###############################################################
#  Generated by:      Cadence Innovus 21.35-s114_1
#  OS:                Linux x86_64(Host ID pc231.ee.hacettepe.edu.tr)
#  Generated on:      Wed Dec 24 12:11:23 2025
#  Design:            memory_macro
#  Command:           write_lef_abstract -5.7 outputs/memory_macro/memory_macro.lef
###############################################################

VERSION 5.7 ;

BUSBITCHARS "[]" ;
DIVIDERCHAR "/" ;

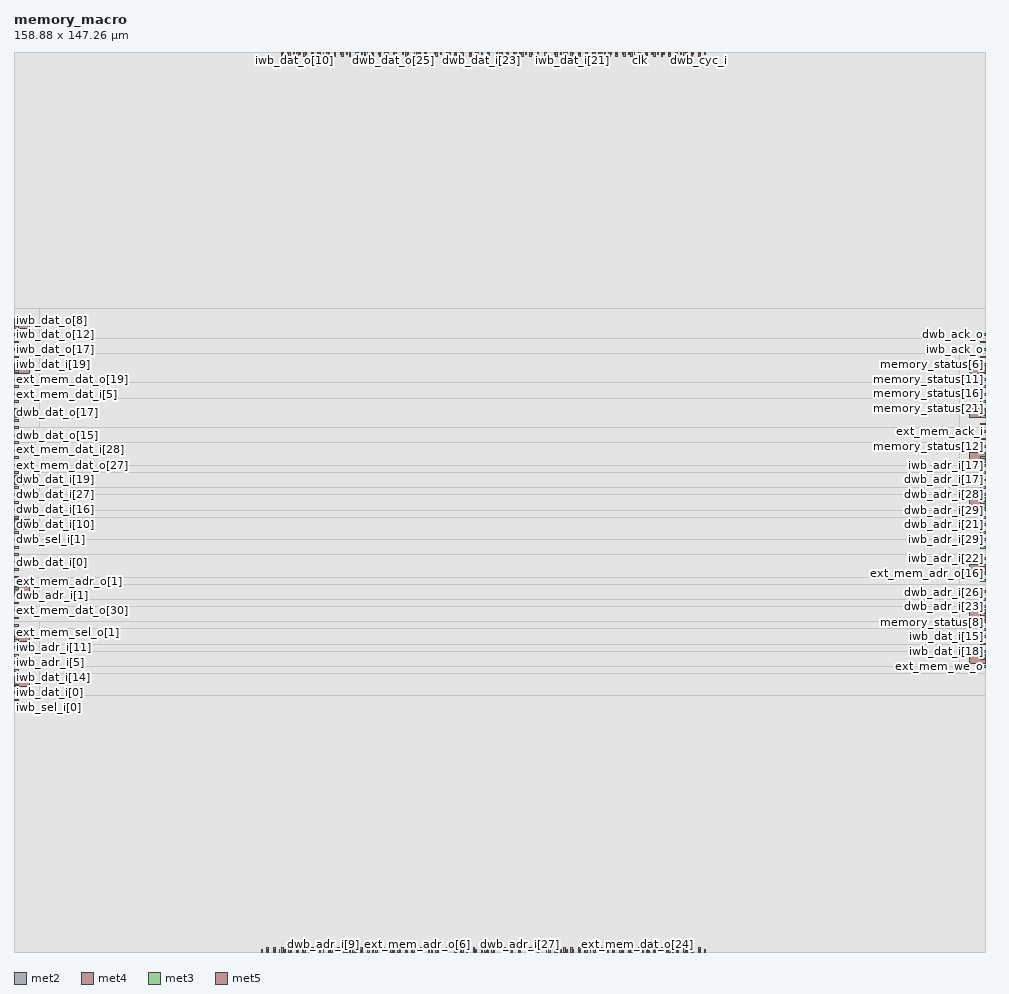
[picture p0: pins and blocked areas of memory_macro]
MACRO memory_macro
  CLASS BLOCK ;
  SIZE 158.880000 BY 147.260000 ;
  FOREIGN memory_macro 0.000000 0.000000 ;
  ORIGIN 0 0 ;
  SYMMETRY X Y R90 ;
  PIN clk
    DIRECTION INPUT ;
    USE SIGNAL ;
    PORT
      LAYER met2 ;
        RECT 102.410000 146.775000 102.550000 147.260000 ;
    END
  END clk
  PIN rst_n
    DIRECTION INPUT ;
    USE SIGNAL ;
    PORT
      LAYER met4 ;
        RECT 109.560000 146.460000 109.860000 147.260000 ;
    END
  END rst_n
  PIN iwb_adr_i[31]
    DIRECTION INPUT ;
    USE SIGNAL ;
    PORT
      LAYER met2 ;
        RECT 85.610000 146.775000 85.750000 147.260000 ;
    END
  END iwb_adr_i[31]
  PIN iwb_adr_i[30]
    DIRECTION INPUT ;
    USE SIGNAL ;
    PORT
      LAYER met4 ;
        RECT 96.030000 0.000000 96.330000 0.800000 ;
    END
  END iwb_adr_i[30]
  PIN iwb_adr_i[29]
    DIRECTION INPUT ;
    USE SIGNAL ;
    PORT
      LAYER met3 ;
        RECT 158.080000 68.540000 158.880000 68.840000 ;
    END
  END iwb_adr_i[29]
  PIN iwb_adr_i[28]
    DIRECTION INPUT ;
    USE SIGNAL ;
    PORT
      LAYER met3 ;
        RECT 158.080000 78.300000 158.880000 78.600000 ;
    END
  END iwb_adr_i[28]
  PIN iwb_adr_i[27]
    DIRECTION INPUT ;
    USE SIGNAL ;
    PORT
      LAYER met3 ;
        RECT 158.080000 67.320000 158.880000 67.620000 ;
    END
  END iwb_adr_i[27]
  PIN iwb_adr_i[26]
    DIRECTION INPUT ;
    USE SIGNAL ;
    PORT
      LAYER met4 ;
        RECT 99.105000 0.000000 99.405000 0.800000 ;
    END
  END iwb_adr_i[26]
  PIN iwb_adr_i[25]
    DIRECTION INPUT ;
    USE SIGNAL ;
    PORT
      LAYER met4 ;
        RECT 102.180000 0.000000 102.480000 0.800000 ;
    END
  END iwb_adr_i[25]
  PIN iwb_adr_i[24]
    DIRECTION INPUT ;
    USE SIGNAL ;
    PORT
      LAYER met2 ;
        RECT 102.890000 0.000000 103.030000 0.485000 ;
    END
  END iwb_adr_i[24]
  PIN iwb_adr_i[23]
    DIRECTION INPUT ;
    USE SIGNAL ;
    PORT
      LAYER met4 ;
        RECT 103.410000 0.000000 103.710000 0.800000 ;
    END
  END iwb_adr_i[23]
  PIN iwb_adr_i[22]
    DIRECTION INPUT ;
    USE SIGNAL ;
    PORT
      LAYER met3 ;
        RECT 158.080000 64.270000 158.880000 64.570000 ;
    END
  END iwb_adr_i[22]
  PIN iwb_adr_i[21]
    DIRECTION INPUT ;
    USE SIGNAL ;
    PORT
      LAYER met3 ;
        RECT 158.080000 66.100000 158.880000 66.400000 ;
    END
  END iwb_adr_i[21]
  PIN iwb_adr_i[20]
    DIRECTION INPUT ;
    USE SIGNAL ;
    PORT
      LAYER met4 ;
        RECT 85.575000 146.460000 85.875000 147.260000 ;
    END
  END iwb_adr_i[20]
  PIN iwb_adr_i[19]
    DIRECTION INPUT ;
    USE SIGNAL ;
    PORT
      LAYER met3 ;
        RECT 158.080000 55.120000 158.880000 55.420000 ;
    END
  END iwb_adr_i[19]
  PIN iwb_adr_i[18]
    DIRECTION INPUT ;
    USE SIGNAL ;
    PORT
      LAYER met5 ;
        RECT 156.380000 54.470000 158.880000 56.070000 ;
    END
  END iwb_adr_i[18]
  PIN iwb_adr_i[17]
    DIRECTION INPUT ;
    USE SIGNAL ;
    PORT
      LAYER met3 ;
        RECT 158.080000 79.520000 158.880000 79.820000 ;
    END
  END iwb_adr_i[17]
  PIN iwb_adr_i[16]
    DIRECTION INPUT ;
    USE SIGNAL ;
    PORT
      LAYER met4 ;
        RECT 104.640000 0.000000 104.940000 0.800000 ;
    END
  END iwb_adr_i[16]
  PIN iwb_adr_i[15]
    DIRECTION INPUT ;
    USE SIGNAL ;
    PORT
      LAYER met4 ;
        RECT 105.870000 0.000000 106.170000 0.800000 ;
    END
  END iwb_adr_i[15]
  PIN iwb_adr_i[14]
    DIRECTION INPUT ;
    USE SIGNAL ;
    PORT
      LAYER met4 ;
        RECT 51.750000 0.000000 52.050000 0.800000 ;
    END
  END iwb_adr_i[14]
  PIN iwb_adr_i[13]
    DIRECTION INPUT ;
    USE SIGNAL ;
    PORT
      LAYER met5 ;
        RECT 0.000000 50.810000 2.500000 52.410000 ;
    END
  END iwb_adr_i[13]
  PIN iwb_adr_i[12]
    DIRECTION INPUT ;
    USE SIGNAL ;
    PORT
      LAYER met2 ;
        RECT 51.530000 0.000000 51.670000 0.485000 ;
    END
  END iwb_adr_i[12]
  PIN iwb_adr_i[11]
    DIRECTION INPUT ;
    USE SIGNAL ;
    PORT
      LAYER met3 ;
        RECT 0.000000 50.850000 0.800000 51.150000 ;
    END
  END iwb_adr_i[11]
  PIN iwb_adr_i[10]
    DIRECTION INPUT ;
    USE SIGNAL ;
    PORT
      LAYER met2 ;
        RECT 106.730000 0.000000 106.870000 0.485000 ;
    END
  END iwb_adr_i[10]
  PIN iwb_adr_i[9]
    DIRECTION INPUT ;
    USE SIGNAL ;
    PORT
      LAYER met3 ;
        RECT 0.000000 49.630000 0.800000 49.930000 ;
    END
  END iwb_adr_i[9]
  PIN iwb_adr_i[8]
    DIRECTION INPUT ;
    USE SIGNAL ;
    PORT
      LAYER met3 ;
        RECT 0.000000 93.550000 0.800000 93.850000 ;
    END
  END iwb_adr_i[8]
  PIN iwb_adr_i[7]
    DIRECTION INPUT ;
    USE SIGNAL ;
    PORT
      LAYER met4 ;
        RECT 107.100000 0.000000 107.400000 0.800000 ;
    END
  END iwb_adr_i[7]
  PIN iwb_adr_i[6]
    DIRECTION INPUT ;
    USE SIGNAL ;
    PORT
      LAYER met4 ;
        RECT 48.675000 0.000000 48.975000 0.800000 ;
    END
  END iwb_adr_i[6]
  PIN iwb_adr_i[5]
    DIRECTION INPUT ;
    USE SIGNAL ;
    PORT
      LAYER met3 ;
        RECT 0.000000 48.410000 0.800000 48.710000 ;
    END
  END iwb_adr_i[5]
  PIN iwb_adr_i[4]
    DIRECTION INPUT ;
    USE SIGNAL ;
    PORT
      LAYER met2 ;
        RECT 48.170000 0.000000 48.310000 0.485000 ;
    END
  END iwb_adr_i[4]
  PIN iwb_adr_i[3]
    DIRECTION INPUT ;
    USE SIGNAL ;
    PORT
      LAYER met2 ;
        RECT 108.650000 0.000000 108.790000 0.485000 ;
    END
  END iwb_adr_i[3]
  PIN iwb_adr_i[2]
    DIRECTION INPUT ;
    USE SIGNAL ;
    PORT
      LAYER met4 ;
        RECT 108.330000 0.000000 108.630000 0.800000 ;
    END
  END iwb_adr_i[2]
  PIN iwb_adr_i[1]
    DIRECTION INPUT ;
    USE SIGNAL ;
    PORT
      LAYER met4 ;
        RECT 47.445000 0.000000 47.745000 0.800000 ;
    END
  END iwb_adr_i[1]
  PIN iwb_adr_i[0]
    DIRECTION INPUT ;
    USE SIGNAL ;
    PORT
      LAYER met4 ;
        RECT 109.560000 0.000000 109.860000 0.800000 ;
    END
  END iwb_adr_i[0]
  PIN iwb_dat_o[31]
    DIRECTION OUTPUT ;
    USE SIGNAL ;
    PORT
      LAYER met4 ;
        RECT 91.110000 146.460000 91.410000 147.260000 ;
    END
  END iwb_dat_o[31]
  PIN iwb_dat_o[30]
    DIRECTION OUTPUT ;
    USE SIGNAL ;
    PORT
      LAYER met4 ;
        RECT 49.905000 146.460000 50.205000 147.260000 ;
    END
  END iwb_dat_o[30]
  PIN iwb_dat_o[29]
    DIRECTION OUTPUT ;
    USE SIGNAL ;
    PORT
      LAYER met2 ;
        RECT 49.610000 146.775000 49.750000 147.260000 ;
    END
  END iwb_dat_o[29]
  PIN iwb_dat_o[28]
    DIRECTION OUTPUT ;
    USE SIGNAL ;
    PORT
      LAYER met3 ;
        RECT 0.000000 97.210000 0.800000 97.510000 ;
    END
  END iwb_dat_o[28]
  PIN iwb_dat_o[27]
    DIRECTION OUTPUT ;
    USE SIGNAL ;
    PORT
      LAYER met2 ;
        RECT 92.330000 146.775000 92.470000 147.260000 ;
    END
  END iwb_dat_o[27]
  PIN iwb_dat_o[26]
    DIRECTION OUTPUT ;
    USE SIGNAL ;
    PORT
      LAYER met4 ;
        RECT 92.340000 146.460000 92.640000 147.260000 ;
    END
  END iwb_dat_o[26]
  PIN iwb_dat_o[25]
    DIRECTION OUTPUT ;
    USE SIGNAL ;
    PORT
      LAYER met2 ;
        RECT 48.650000 146.775000 48.790000 147.260000 ;
    END
  END iwb_dat_o[25]
  PIN iwb_dat_o[24]
    DIRECTION OUTPUT ;
    USE SIGNAL ;
    PORT
      LAYER met4 ;
        RECT 48.675000 146.460000 48.975000 147.260000 ;
    END
  END iwb_dat_o[24]
  PIN iwb_dat_o[23]
    DIRECTION OUTPUT ;
    USE SIGNAL ;
    PORT
      LAYER met4 ;
        RECT 93.570000 146.460000 93.870000 147.260000 ;
    END
  END iwb_dat_o[23]
  PIN iwb_dat_o[22]
    DIRECTION OUTPUT ;
    USE SIGNAL ;
    PORT
      LAYER met2 ;
        RECT 94.730000 146.775000 94.870000 147.260000 ;
    END
  END iwb_dat_o[22]
  PIN iwb_dat_o[21]
    DIRECTION OUTPUT ;
    USE SIGNAL ;
    PORT
      LAYER met3 ;
        RECT 0.000000 98.430000 0.800000 98.730000 ;
    END
  END iwb_dat_o[21]
  PIN iwb_dat_o[20]
    DIRECTION OUTPUT ;
    USE SIGNAL ;
    PORT
      LAYER met2 ;
        RECT 47.690000 146.775000 47.830000 147.260000 ;
    END
  END iwb_dat_o[20]
  PIN iwb_dat_o[19]
    DIRECTION OUTPUT ;
    USE SIGNAL ;
    PORT
      LAYER met4 ;
        RECT 94.800000 146.460000 95.100000 147.260000 ;
    END
  END iwb_dat_o[19]
  PIN iwb_dat_o[18]
    DIRECTION OUTPUT ;
    USE SIGNAL ;
    PORT
      LAYER met4 ;
        RECT 47.445000 146.460000 47.745000 147.260000 ;
    END
  END iwb_dat_o[18]
  PIN iwb_dat_o[17]
    DIRECTION OUTPUT ;
    USE SIGNAL ;
    PORT
      LAYER met3 ;
        RECT 0.000000 99.650000 0.800000 99.950000 ;
    END
  END iwb_dat_o[17]
  PIN iwb_dat_o[16]
    DIRECTION OUTPUT ;
    USE SIGNAL ;
    PORT
      LAYER met4 ;
        RECT 96.030000 146.460000 96.330000 147.260000 ;
    END
  END iwb_dat_o[16]
  PIN iwb_dat_o[15]
    DIRECTION OUTPUT ;
    USE SIGNAL ;
    PORT
      LAYER met2 ;
        RECT 46.730000 146.775000 46.870000 147.260000 ;
    END
  END iwb_dat_o[15]
  PIN iwb_dat_o[14]
    DIRECTION OUTPUT ;
    USE SIGNAL ;
    PORT
      LAYER met2 ;
        RECT 96.650000 146.775000 96.790000 147.260000 ;
    END
  END iwb_dat_o[14]
  PIN iwb_dat_o[13]
    DIRECTION OUTPUT ;
    USE SIGNAL ;
    PORT
      LAYER met4 ;
        RECT 46.215000 146.460000 46.515000 147.260000 ;
    END
  END iwb_dat_o[13]
  PIN iwb_dat_o[12]
    DIRECTION OUTPUT ;
    USE SIGNAL ;
    PORT
      LAYER met3 ;
        RECT 0.000000 100.870000 0.800000 101.170000 ;
    END
  END iwb_dat_o[12]
  PIN iwb_dat_o[11]
    DIRECTION OUTPUT ;
    USE SIGNAL ;
    PORT
      LAYER met4 ;
        RECT 97.260000 146.460000 97.560000 147.260000 ;
    END
  END iwb_dat_o[11]
  PIN iwb_dat_o[10]
    DIRECTION OUTPUT ;
    USE SIGNAL ;
    PORT
      LAYER met2 ;
        RECT 45.770000 146.775000 45.910000 147.260000 ;
    END
  END iwb_dat_o[10]
  PIN iwb_dat_o[9]
    DIRECTION OUTPUT ;
    USE SIGNAL ;
    PORT
      LAYER met4 ;
        RECT 44.985000 146.460000 45.285000 147.260000 ;
    END
  END iwb_dat_o[9]
  PIN iwb_dat_o[8]
    DIRECTION OUTPUT ;
    USE SIGNAL ;
    PORT
      LAYER met3 ;
        RECT 0.000000 102.090000 0.800000 102.390000 ;
    END
  END iwb_dat_o[8]
  PIN iwb_dat_o[7]
    DIRECTION OUTPUT ;
    USE SIGNAL ;
    PORT
      LAYER met2 ;
        RECT 97.610000 146.775000 97.750000 147.260000 ;
    END
  END iwb_dat_o[7]
  PIN iwb_dat_o[6]
    DIRECTION OUTPUT ;
    USE SIGNAL ;
    PORT
      LAYER met2 ;
        RECT 44.810000 146.775000 44.950000 147.260000 ;
    END
  END iwb_dat_o[6]
  PIN iwb_dat_o[5]
    DIRECTION OUTPUT ;
    USE SIGNAL ;
    PORT
      LAYER met5 ;
        RECT 0.000000 102.050000 2.500000 103.650000 ;
    END
  END iwb_dat_o[5]
  PIN iwb_dat_o[4]
    DIRECTION OUTPUT ;
    USE SIGNAL ;
    PORT
      LAYER met2 ;
        RECT 98.570000 146.775000 98.710000 147.260000 ;
    END
  END iwb_dat_o[4]
  PIN iwb_dat_o[3]
    DIRECTION OUTPUT ;
    USE SIGNAL ;
    PORT
      LAYER met2 ;
        RECT 43.850000 146.775000 43.990000 147.260000 ;
    END
  END iwb_dat_o[3]
  PIN iwb_dat_o[2]
    DIRECTION OUTPUT ;
    USE SIGNAL ;
    PORT
      LAYER met4 ;
        RECT 43.755000 146.460000 44.055000 147.260000 ;
    END
  END iwb_dat_o[2]
  PIN iwb_dat_o[1]
    DIRECTION OUTPUT ;
    USE SIGNAL ;
    PORT
      LAYER met4 ;
        RECT 98.490000 146.460000 98.790000 147.260000 ;
    END
  END iwb_dat_o[1]
  PIN iwb_dat_o[0]
    DIRECTION OUTPUT ;
    USE SIGNAL ;
    PORT
      LAYER met2 ;
        RECT 99.530000 146.775000 99.670000 147.260000 ;
    END
  END iwb_dat_o[0]
  PIN iwb_dat_i[31]
    DIRECTION INPUT ;
    USE SIGNAL ;
    PORT
      LAYER met3 ;
        RECT 0.000000 47.190000 0.800000 47.490000 ;
    END
  END iwb_dat_i[31]
  PIN iwb_dat_i[30]
    DIRECTION INPUT ;
    USE SIGNAL ;
    PORT
      LAYER met2 ;
        RECT 47.210000 0.000000 47.350000 0.485000 ;
    END
  END iwb_dat_i[30]
  PIN iwb_dat_i[29]
    DIRECTION INPUT ;
    USE SIGNAL ;
    PORT
      LAYER met2 ;
        RECT 52.490000 146.775000 52.630000 147.260000 ;
    END
  END iwb_dat_i[29]
  PIN iwb_dat_i[28]
    DIRECTION INPUT ;
    USE SIGNAL ;
    PORT
      LAYER met2 ;
        RECT 46.250000 0.000000 46.390000 0.485000 ;
    END
  END iwb_dat_i[28]
  PIN iwb_dat_i[27]
    DIRECTION INPUT ;
    USE SIGNAL ;
    PORT
      LAYER met4 ;
        RECT 52.365000 146.460000 52.665000 147.260000 ;
    END
  END iwb_dat_i[27]
  PIN iwb_dat_i[26]
    DIRECTION INPUT ;
    USE SIGNAL ;
    PORT
      LAYER met4 ;
        RECT 46.215000 0.000000 46.515000 0.800000 ;
    END
  END iwb_dat_i[26]
  PIN iwb_dat_i[25]
    DIRECTION INPUT ;
    USE SIGNAL ;
    PORT
      LAYER met3 ;
        RECT 158.080000 50.240000 158.880000 50.540000 ;
    END
  END iwb_dat_i[25]
  PIN iwb_dat_i[24]
    DIRECTION INPUT ;
    USE SIGNAL ;
    PORT
      LAYER met2 ;
        RECT 111.050000 0.000000 111.190000 0.485000 ;
    END
  END iwb_dat_i[24]
  PIN iwb_dat_i[23]
    DIRECTION INPUT ;
    USE SIGNAL ;
    PORT
      LAYER met4 ;
        RECT 89.880000 146.460000 90.180000 147.260000 ;
    END
  END iwb_dat_i[23]
  PIN iwb_dat_i[22]
    DIRECTION INPUT ;
    USE SIGNAL ;
    PORT
      LAYER met2 ;
        RECT 45.290000 0.000000 45.430000 0.485000 ;
    END
  END iwb_dat_i[22]
  PIN iwb_dat_i[21]
    DIRECTION INPUT ;
    USE SIGNAL ;
    PORT
      LAYER met2 ;
        RECT 91.370000 146.775000 91.510000 147.260000 ;
    END
  END iwb_dat_i[21]
  PIN iwb_dat_i[20]
    DIRECTION INPUT ;
    USE SIGNAL ;
    PORT
      LAYER met3 ;
        RECT 0.000000 45.970000 0.800000 46.270000 ;
    END
  END iwb_dat_i[20]
  PIN iwb_dat_i[19]
    DIRECTION INPUT ;
    USE SIGNAL ;
    PORT
      LAYER met3 ;
        RECT 0.000000 94.770000 0.800000 95.070000 ;
    END
  END iwb_dat_i[19]
  PIN iwb_dat_i[18]
    DIRECTION INPUT ;
    USE SIGNAL ;
    PORT
      LAYER met3 ;
        RECT 158.080000 49.020000 158.880000 49.320000 ;
    END
  END iwb_dat_i[18]
  PIN iwb_dat_i[17]
    DIRECTION INPUT ;
    USE SIGNAL ;
    PORT
      LAYER met4 ;
        RECT 44.985000 0.000000 45.285000 0.800000 ;
    END
  END iwb_dat_i[17]
  PIN iwb_dat_i[16]
    DIRECTION INPUT ;
    USE SIGNAL ;
    PORT
      LAYER met5 ;
        RECT 0.000000 94.730000 2.500000 96.330000 ;
    END
  END iwb_dat_i[16]
  PIN iwb_dat_i[15]
    DIRECTION INPUT ;
    USE SIGNAL ;
    PORT
      LAYER met3 ;
        RECT 158.080000 51.460000 158.880000 51.760000 ;
    END
  END iwb_dat_i[15]
  PIN iwb_dat_i[14]
    DIRECTION INPUT ;
    USE SIGNAL ;
    PORT
      LAYER met3 ;
        RECT 0.000000 44.750000 0.800000 45.050000 ;
    END
  END iwb_dat_i[14]
  PIN iwb_dat_i[13]
    DIRECTION INPUT ;
    USE SIGNAL ;
    PORT
      LAYER met2 ;
        RECT 44.330000 0.000000 44.470000 0.485000 ;
    END
  END iwb_dat_i[13]
  PIN iwb_dat_i[12]
    DIRECTION INPUT ;
    USE SIGNAL ;
    PORT
      LAYER met2 ;
        RECT 51.530000 146.775000 51.670000 147.260000 ;
    END
  END iwb_dat_i[12]
  PIN iwb_dat_i[11]
    DIRECTION INPUT ;
    USE SIGNAL ;
    PORT
      LAYER met4 ;
        RECT 110.790000 0.000000 111.090000 0.800000 ;
    END
  END iwb_dat_i[11]
  PIN iwb_dat_i[10]
    DIRECTION INPUT ;
    USE SIGNAL ;
    PORT
      LAYER met4 ;
        RECT 51.135000 146.460000 51.435000 147.260000 ;
    END
  END iwb_dat_i[10]
  PIN iwb_dat_i[9]
    DIRECTION INPUT ;
    USE SIGNAL ;
    PORT
      LAYER met4 ;
        RECT 43.755000 0.000000 44.055000 0.800000 ;
    END
  END iwb_dat_i[9]
  PIN iwb_dat_i[8]
    DIRECTION INPUT ;
    USE SIGNAL ;
    PORT
      LAYER met3 ;
        RECT 0.000000 43.530000 0.800000 43.830000 ;
    END
  END iwb_dat_i[8]
  PIN iwb_dat_i[7]
    DIRECTION INPUT ;
    USE SIGNAL ;
    PORT
      LAYER met5 ;
        RECT 0.000000 43.490000 2.500000 45.090000 ;
    END
  END iwb_dat_i[7]
  PIN iwb_dat_i[6]
    DIRECTION INPUT ;
    USE SIGNAL ;
    PORT
      LAYER met3 ;
        RECT 0.000000 95.990000 0.800000 96.290000 ;
    END
  END iwb_dat_i[6]
  PIN iwb_dat_i[5]
    DIRECTION INPUT ;
    USE SIGNAL ;
    PORT
      LAYER met2 ;
        RECT 50.570000 146.775000 50.710000 147.260000 ;
    END
  END iwb_dat_i[5]
  PIN iwb_dat_i[4]
    DIRECTION INPUT ;
    USE SIGNAL ;
    PORT
      LAYER met2 ;
        RECT 43.370000 0.000000 43.510000 0.485000 ;
    END
  END iwb_dat_i[4]
  PIN iwb_dat_i[3]
    DIRECTION INPUT ;
    USE SIGNAL ;
    PORT
      LAYER met3 ;
        RECT 158.080000 47.800000 158.880000 48.100000 ;
    END
  END iwb_dat_i[3]
  PIN iwb_dat_i[2]
    DIRECTION INPUT ;
    USE SIGNAL ;
    PORT
      LAYER met2 ;
        RECT 42.410000 0.000000 42.550000 0.485000 ;
    END
  END iwb_dat_i[2]
  PIN iwb_dat_i[1]
    DIRECTION INPUT ;
    USE SIGNAL ;
    PORT
      LAYER met4 ;
        RECT 42.525000 0.000000 42.825000 0.800000 ;
    END
  END iwb_dat_i[1]
  PIN iwb_dat_i[0]
    DIRECTION INPUT ;
    USE SIGNAL ;
    PORT
      LAYER met3 ;
        RECT 0.000000 42.310000 0.800000 42.610000 ;
    END
  END iwb_dat_i[0]
  PIN iwb_we_i
    DIRECTION INPUT ;
    USE SIGNAL ;
    PORT
      LAYER met2 ;
        RECT 40.490000 0.000000 40.630000 0.485000 ;
    END
  END iwb_we_i
  PIN iwb_sel_i[3]
    DIRECTION INPUT ;
    USE SIGNAL ;
    PORT
      LAYER met2 ;
        RECT 112.010000 0.000000 112.150000 0.485000 ;
    END
  END iwb_sel_i[3]
  PIN iwb_sel_i[2]
    DIRECTION INPUT ;
    USE SIGNAL ;
    PORT
      LAYER met2 ;
        RECT 41.450000 0.000000 41.590000 0.485000 ;
    END
  END iwb_sel_i[2]
  PIN iwb_sel_i[1]
    DIRECTION INPUT ;
    USE SIGNAL ;
    PORT
      LAYER met4 ;
        RECT 41.295000 0.000000 41.595000 0.800000 ;
    END
  END iwb_sel_i[1]
  PIN iwb_sel_i[0]
    DIRECTION INPUT ;
    USE SIGNAL ;
    PORT
      LAYER met3 ;
        RECT 0.000000 41.090000 0.800000 41.390000 ;
    END
  END iwb_sel_i[0]
  PIN iwb_cyc_i
    DIRECTION INPUT ;
    USE SIGNAL ;
    PORT
      LAYER met2 ;
        RECT 111.050000 146.775000 111.190000 147.260000 ;
    END
  END iwb_cyc_i
  PIN iwb_stb_i
    DIRECTION INPUT ;
    USE SIGNAL ;
    PORT
      LAYER met4 ;
        RECT 110.790000 146.460000 111.090000 147.260000 ;
    END
  END iwb_stb_i
  PIN iwb_ack_o
    DIRECTION OUTPUT ;
    USE SIGNAL ;
    PORT
      LAYER met3 ;
        RECT 158.080000 99.650000 158.880000 99.950000 ;
    END
  END iwb_ack_o
  PIN iwb_err_o
    DIRECTION OUTPUT ;
    USE SIGNAL ;
    PORT
      LAYER met3 ;
        RECT 158.080000 98.430000 158.880000 98.730000 ;
    END
  END iwb_err_o
  PIN dwb_adr_i[31]
    DIRECTION INPUT ;
    USE SIGNAL ;
    PORT
      LAYER met3 ;
        RECT 158.080000 82.570000 158.880000 82.870000 ;
    END
  END dwb_adr_i[31]
  PIN dwb_adr_i[30]
    DIRECTION INPUT ;
    USE SIGNAL ;
    PORT
      LAYER met2 ;
        RECT 84.170000 0.000000 84.310000 0.485000 ;
    END
  END dwb_adr_i[30]
  PIN dwb_adr_i[29]
    DIRECTION INPUT ;
    USE SIGNAL ;
    PORT
      LAYER met3 ;
        RECT 158.080000 70.980000 158.880000 71.280000 ;
    END
  END dwb_adr_i[29]
  PIN dwb_adr_i[28]
    DIRECTION INPUT ;
    USE SIGNAL ;
    PORT
      LAYER met3 ;
        RECT 158.080000 75.860000 158.880000 76.160000 ;
    END
  END dwb_adr_i[28]
  PIN dwb_adr_i[27]
    DIRECTION INPUT ;
    USE SIGNAL ;
    PORT
      LAYER met2 ;
        RECT 82.730000 0.000000 82.870000 0.485000 ;
    END
  END dwb_adr_i[27]
  PIN dwb_adr_i[26]
    DIRECTION INPUT ;
    USE SIGNAL ;
    PORT
      LAYER met3 ;
        RECT 158.080000 57.560000 158.880000 57.860000 ;
    END
  END dwb_adr_i[26]
  PIN dwb_adr_i[25]
    DIRECTION INPUT ;
    USE SIGNAL ;
    PORT
      LAYER met2 ;
        RECT 89.450000 0.000000 89.590000 0.485000 ;
    END
  END dwb_adr_i[25]
  PIN dwb_adr_i[24]
    DIRECTION INPUT ;
    USE SIGNAL ;
    PORT
      LAYER met2 ;
        RECT 91.370000 0.000000 91.510000 0.485000 ;
    END
  END dwb_adr_i[24]
  PIN dwb_adr_i[23]
    DIRECTION INPUT ;
    USE SIGNAL ;
    PORT
      LAYER met3 ;
        RECT 158.080000 56.340000 158.880000 56.640000 ;
    END
  END dwb_adr_i[23]
  PIN dwb_adr_i[22]
    DIRECTION INPUT ;
    USE SIGNAL ;
    PORT
      LAYER met4 ;
        RECT 88.650000 0.000000 88.950000 0.800000 ;
    END
  END dwb_adr_i[22]
  PIN dwb_adr_i[21]
    DIRECTION INPUT ;
    USE SIGNAL ;
    PORT
      LAYER met3 ;
        RECT 158.080000 69.760000 158.880000 70.060000 ;
    END
  END dwb_adr_i[21]
  PIN dwb_adr_i[20]
    DIRECTION INPUT ;
    USE SIGNAL ;
    PORT
      LAYER met2 ;
        RECT 79.850000 0.000000 79.990000 0.485000 ;
    END
  END dwb_adr_i[20]
  PIN dwb_adr_i[19]
    DIRECTION INPUT ;
    USE SIGNAL ;
    PORT
      LAYER met3 ;
        RECT 158.080000 63.050000 158.880000 63.350000 ;
    END
  END dwb_adr_i[19]
  PIN dwb_adr_i[18]
    DIRECTION INPUT ;
    USE SIGNAL ;
    PORT
      LAYER met2 ;
        RECT 81.290000 0.000000 81.430000 0.485000 ;
    END
  END dwb_adr_i[18]
  PIN dwb_adr_i[17]
    DIRECTION INPUT ;
    USE SIGNAL ;
    PORT
      LAYER met3 ;
        RECT 158.080000 77.080000 158.880000 77.380000 ;
    END
  END dwb_adr_i[17]
  PIN dwb_adr_i[16]
    DIRECTION INPUT ;
    USE SIGNAL ;
    PORT
      LAYER met5 ;
        RECT 156.380000 61.790000 158.880000 63.390000 ;
    END
  END dwb_adr_i[16]
  PIN dwb_adr_i[15]
    DIRECTION INPUT ;
    USE SIGNAL ;
    PORT
      LAYER met2 ;
        RECT 99.530000 0.000000 99.670000 0.485000 ;
    END
  END dwb_adr_i[15]
  PIN dwb_adr_i[14]
    DIRECTION INPUT ;
    USE SIGNAL ;
    PORT
      LAYER met2 ;
        RECT 60.170000 0.000000 60.310000 0.485000 ;
    END
  END dwb_adr_i[14]
  PIN dwb_adr_i[13]
    DIRECTION INPUT ;
    USE SIGNAL ;
    PORT
      LAYER met2 ;
        RECT 75.530000 0.000000 75.670000 0.485000 ;
    END
  END dwb_adr_i[13]
  PIN dwb_adr_i[12]
    DIRECTION INPUT ;
    USE SIGNAL ;
    PORT
      LAYER met2 ;
        RECT 64.010000 0.000000 64.150000 0.485000 ;
    END
  END dwb_adr_i[12]
  PIN dwb_adr_i[11]
    DIRECTION INPUT ;
    USE SIGNAL ;
    PORT
      LAYER met2 ;
        RECT 72.170000 0.000000 72.310000 0.485000 ;
    END
  END dwb_adr_i[11]
  PIN dwb_adr_i[10]
    DIRECTION INPUT ;
    USE SIGNAL ;
    PORT
      LAYER met2 ;
        RECT 87.050000 0.000000 87.190000 0.485000 ;
    END
  END dwb_adr_i[10]
  PIN dwb_adr_i[9]
    DIRECTION INPUT ;
    USE SIGNAL ;
    PORT
      LAYER met2 ;
        RECT 50.570000 0.000000 50.710000 0.485000 ;
    END
  END dwb_adr_i[9]
  PIN dwb_adr_i[8]
    DIRECTION INPUT ;
    USE SIGNAL ;
    PORT
      LAYER met2 ;
        RECT 72.170000 146.775000 72.310000 147.260000 ;
    END
  END dwb_adr_i[8]
  PIN dwb_adr_i[7]
    DIRECTION INPUT ;
    USE SIGNAL ;
    PORT
      LAYER met2 ;
        RECT 107.690000 0.000000 107.830000 0.485000 ;
    END
  END dwb_adr_i[7]
  PIN dwb_adr_i[6]
    DIRECTION INPUT ;
    USE SIGNAL ;
    PORT
      LAYER met2 ;
        RECT 68.330000 0.000000 68.470000 0.485000 ;
    END
  END dwb_adr_i[6]
  PIN dwb_adr_i[5]
    DIRECTION INPUT ;
    USE SIGNAL ;
    PORT
      LAYER met2 ;
        RECT 66.890000 0.000000 67.030000 0.485000 ;
    END
  END dwb_adr_i[5]
  PIN dwb_adr_i[4]
    DIRECTION INPUT ;
    USE SIGNAL ;
    PORT
      LAYER met4 ;
        RECT 60.360000 0.000000 60.660000 0.800000 ;
    END
  END dwb_adr_i[4]
  PIN dwb_adr_i[3]
    DIRECTION INPUT ;
    USE SIGNAL ;
    PORT
      LAYER met2 ;
        RECT 95.690000 0.000000 95.830000 0.485000 ;
    END
  END dwb_adr_i[3]
  PIN dwb_adr_i[2]
    DIRECTION INPUT ;
    USE SIGNAL ;
    PORT
      LAYER met4 ;
        RECT 91.110000 0.000000 91.410000 0.800000 ;
    END
  END dwb_adr_i[2]
  PIN dwb_adr_i[1]
    DIRECTION INPUT ;
    USE SIGNAL ;
    PORT
      LAYER met3 ;
        RECT 0.000000 58.170000 0.800000 58.470000 ;
    END
  END dwb_adr_i[1]
  PIN dwb_adr_i[0]
    DIRECTION INPUT ;
    USE SIGNAL ;
    PORT
      LAYER met4 ;
        RECT 82.500000 0.000000 82.800000 0.800000 ;
    END
  END dwb_adr_i[0]
  PIN dwb_dat_o[31]
    DIRECTION OUTPUT ;
    USE SIGNAL ;
    PORT
      LAYER met4 ;
        RECT 75.735000 146.460000 76.035000 147.260000 ;
    END
  END dwb_dat_o[31]
  PIN dwb_dat_o[30]
    DIRECTION OUTPUT ;
    USE SIGNAL ;
    PORT
      LAYER met2 ;
        RECT 67.370000 146.775000 67.510000 147.260000 ;
    END
  END dwb_dat_o[30]
  PIN dwb_dat_o[29]
    DIRECTION OUTPUT ;
    USE SIGNAL ;
    PORT
      LAYER met2 ;
        RECT 58.730000 146.775000 58.870000 147.260000 ;
    END
  END dwb_dat_o[29]
  PIN dwb_dat_o[28]
    DIRECTION OUTPUT ;
    USE SIGNAL ;
    PORT
      LAYER met3 ;
        RECT 0.000000 85.620000 0.800000 85.920000 ;
    END
  END dwb_dat_o[28]
  PIN dwb_dat_o[27]
    DIRECTION OUTPUT ;
    USE SIGNAL ;
    PORT
      LAYER met2 ;
        RECT 78.890000 146.775000 79.030000 147.260000 ;
    END
  END dwb_dat_o[27]
  PIN dwb_dat_o[26]
    DIRECTION OUTPUT ;
    USE SIGNAL ;
    PORT
      LAYER met4 ;
        RECT 79.425000 146.460000 79.725000 147.260000 ;
    END
  END dwb_dat_o[26]
  PIN dwb_dat_o[25]
    DIRECTION OUTPUT ;
    USE SIGNAL ;
    PORT
      LAYER met2 ;
        RECT 62.090000 146.775000 62.230000 147.260000 ;
    END
  END dwb_dat_o[25]
  PIN dwb_dat_o[24]
    DIRECTION OUTPUT ;
    USE SIGNAL ;
    PORT
      LAYER met2 ;
        RECT 73.130000 146.775000 73.270000 147.260000 ;
    END
  END dwb_dat_o[24]
  PIN dwb_dat_o[23]
    DIRECTION OUTPUT ;
    USE SIGNAL ;
    PORT
      LAYER met2 ;
        RECT 88.490000 146.775000 88.630000 147.260000 ;
    END
  END dwb_dat_o[23]
  PIN dwb_dat_o[22]
    DIRECTION OUTPUT ;
    USE SIGNAL ;
    PORT
      LAYER met2 ;
        RECT 77.450000 146.775000 77.590000 147.260000 ;
    END
  END dwb_dat_o[22]
  PIN dwb_dat_o[21]
    DIRECTION OUTPUT ;
    USE SIGNAL ;
    PORT
      LAYER met2 ;
        RECT 53.450000 146.775000 53.590000 147.260000 ;
    END
  END dwb_dat_o[21]
  PIN dwb_dat_o[20]
    DIRECTION OUTPUT ;
    USE SIGNAL ;
    PORT
      LAYER met4 ;
        RECT 62.205000 146.460000 62.505000 147.260000 ;
    END
  END dwb_dat_o[20]
  PIN dwb_dat_o[19]
    DIRECTION OUTPUT ;
    USE SIGNAL ;
    PORT
      LAYER met4 ;
        RECT 88.650000 146.460000 88.950000 147.260000 ;
    END
  END dwb_dat_o[19]
  PIN dwb_dat_o[18]
    DIRECTION OUTPUT ;
    USE SIGNAL ;
    PORT
      LAYER met4 ;
        RECT 67.125000 146.460000 67.425000 147.260000 ;
    END
  END dwb_dat_o[18]
  PIN dwb_dat_o[17]
    DIRECTION OUTPUT ;
    USE SIGNAL ;
    PORT
      LAYER met3 ;
        RECT 0.000000 88.060000 0.800000 88.360000 ;
    END
  END dwb_dat_o[17]
  PIN dwb_dat_o[16]
    DIRECTION OUTPUT ;
    USE SIGNAL ;
    PORT
      LAYER met4 ;
        RECT 77.580000 146.460000 77.880000 147.260000 ;
    END
  END dwb_dat_o[16]
  PIN dwb_dat_o[15]
    DIRECTION OUTPUT ;
    USE SIGNAL ;
    PORT
      LAYER met3 ;
        RECT 0.000000 84.400000 0.800000 84.700000 ;
    END
  END dwb_dat_o[15]
  PIN dwb_dat_o[14]
    DIRECTION OUTPUT ;
    USE SIGNAL ;
    PORT
      LAYER met4 ;
        RECT 73.275000 146.460000 73.575000 147.260000 ;
    END
  END dwb_dat_o[14]
  PIN dwb_dat_o[13]
    DIRECTION OUTPUT ;
    USE SIGNAL ;
    PORT
      LAYER met2 ;
        RECT 68.810000 146.775000 68.950000 147.260000 ;
    END
  END dwb_dat_o[13]
  PIN dwb_dat_o[12]
    DIRECTION OUTPUT ;
    USE SIGNAL ;
    PORT
      LAYER met2 ;
        RECT 63.530000 146.775000 63.670000 147.260000 ;
    END
  END dwb_dat_o[12]
  PIN dwb_dat_o[11]
    DIRECTION OUTPUT ;
    USE SIGNAL ;
    PORT
      LAYER met2 ;
        RECT 81.770000 146.775000 81.910000 147.260000 ;
    END
  END dwb_dat_o[11]
  PIN dwb_dat_o[10]
    DIRECTION OUTPUT ;
    USE SIGNAL ;
    PORT
      LAYER met4 ;
        RECT 68.970000 146.460000 69.270000 147.260000 ;
    END
  END dwb_dat_o[10]
  PIN dwb_dat_o[9]
    DIRECTION OUTPUT ;
    USE SIGNAL ;
    PORT
      LAYER met2 ;
        RECT 60.650000 146.775000 60.790000 147.260000 ;
    END
  END dwb_dat_o[9]
  PIN dwb_dat_o[8]
    DIRECTION OUTPUT ;
    USE SIGNAL ;
    PORT
      LAYER met2 ;
        RECT 66.410000 146.775000 66.550000 147.260000 ;
    END
  END dwb_dat_o[8]
  PIN dwb_dat_o[7]
    DIRECTION OUTPUT ;
    USE SIGNAL ;
    PORT
      LAYER met2 ;
        RECT 95.690000 146.775000 95.830000 147.260000 ;
    END
  END dwb_dat_o[7]
  PIN dwb_dat_o[6]
    DIRECTION OUTPUT ;
    USE SIGNAL ;
    PORT
      LAYER met2 ;
        RECT 57.770000 146.775000 57.910000 147.260000 ;
    END
  END dwb_dat_o[6]
  PIN dwb_dat_o[5]
    DIRECTION OUTPUT ;
    USE SIGNAL ;
    PORT
      LAYER met5 ;
        RECT 0.000000 87.410000 2.500000 89.010000 ;
    END
  END dwb_dat_o[5]
  PIN dwb_dat_o[4]
    DIRECTION OUTPUT ;
    USE SIGNAL ;
    PORT
      LAYER met4 ;
        RECT 81.885000 146.460000 82.185000 147.260000 ;
    END
  END dwb_dat_o[4]
  PIN dwb_dat_o[3]
    DIRECTION OUTPUT ;
    USE SIGNAL ;
    PORT
      LAYER met4 ;
        RECT 65.895000 146.460000 66.195000 147.260000 ;
    END
  END dwb_dat_o[3]
  PIN dwb_dat_o[2]
    DIRECTION OUTPUT ;
    USE SIGNAL ;
    PORT
      LAYER met4 ;
        RECT 53.595000 146.460000 53.895000 147.260000 ;
    END
  END dwb_dat_o[2]
  PIN dwb_dat_o[1]
    DIRECTION OUTPUT ;
    USE SIGNAL ;
    PORT
      LAYER met2 ;
        RECT 87.050000 146.775000 87.190000 147.260000 ;
    END
  END dwb_dat_o[1]
  PIN dwb_dat_o[0]
    DIRECTION OUTPUT ;
    USE SIGNAL ;
    PORT
      LAYER met2 ;
        RECT 79.850000 146.775000 79.990000 147.260000 ;
    END
  END dwb_dat_o[0]
  PIN dwb_dat_i[31]
    DIRECTION INPUT ;
    USE SIGNAL ;
    PORT
      LAYER met2 ;
        RECT 73.130000 0.000000 73.270000 0.485000 ;
    END
  END dwb_dat_i[31]
  PIN dwb_dat_i[30]
    DIRECTION INPUT ;
    USE SIGNAL ;
    PORT
      LAYER met5 ;
        RECT 0.000000 58.130000 2.500000 59.730000 ;
    END
  END dwb_dat_i[30]
  PIN dwb_dat_i[29]
    DIRECTION INPUT ;
    USE SIGNAL ;
    PORT
      LAYER met3 ;
        RECT 0.000000 75.860000 0.800000 76.160000 ;
    END
  END dwb_dat_i[29]
  PIN dwb_dat_i[28]
    DIRECTION INPUT ;
    USE SIGNAL ;
    PORT
      LAYER met2 ;
        RECT 55.850000 0.000000 55.990000 0.485000 ;
    END
  END dwb_dat_i[28]
  PIN dwb_dat_i[27]
    DIRECTION INPUT ;
    USE SIGNAL ;
    PORT
      LAYER met3 ;
        RECT 0.000000 74.640000 0.800000 74.940000 ;
    END
  END dwb_dat_i[27]
  PIN dwb_dat_i[26]
    DIRECTION INPUT ;
    USE SIGNAL ;
    PORT
      LAYER met3 ;
        RECT 0.000000 70.980000 0.800000 71.280000 ;
    END
  END dwb_dat_i[26]
  PIN dwb_dat_i[25]
    DIRECTION INPUT ;
    USE SIGNAL ;
    PORT
      LAYER met4 ;
        RECT 80.040000 0.000000 80.340000 0.800000 ;
    END
  END dwb_dat_i[25]
  PIN dwb_dat_i[24]
    DIRECTION INPUT ;
    USE SIGNAL ;
    PORT
      LAYER met2 ;
        RECT 100.490000 0.000000 100.630000 0.485000 ;
    END
  END dwb_dat_i[24]
  PIN dwb_dat_i[23]
    DIRECTION INPUT ;
    USE SIGNAL ;
    PORT
      LAYER met2 ;
        RECT 76.490000 146.775000 76.630000 147.260000 ;
    END
  END dwb_dat_i[23]
  PIN dwb_dat_i[22]
    DIRECTION INPUT ;
    USE SIGNAL ;
    PORT
      LAYER met2 ;
        RECT 69.290000 0.000000 69.430000 0.485000 ;
    END
  END dwb_dat_i[22]
  PIN dwb_dat_i[21]
    DIRECTION INPUT ;
    USE SIGNAL ;
    PORT
      LAYER met4 ;
        RECT 75.120000 0.000000 75.420000 0.800000 ;
    END
  END dwb_dat_i[21]
  PIN dwb_dat_i[20]
    DIRECTION INPUT ;
    USE SIGNAL ;
    PORT
      LAYER met2 ;
        RECT 70.730000 0.000000 70.870000 0.485000 ;
    END
  END dwb_dat_i[20]
  PIN dwb_dat_i[19]
    DIRECTION INPUT ;
    USE SIGNAL ;
    PORT
      LAYER met3 ;
        RECT 0.000000 77.080000 0.800000 77.380000 ;
    END
  END dwb_dat_i[19]
  PIN dwb_dat_i[18]
    DIRECTION INPUT ;
    USE SIGNAL ;
    PORT
      LAYER met2 ;
        RECT 103.850000 0.000000 103.990000 0.485000 ;
    END
  END dwb_dat_i[18]
  PIN dwb_dat_i[17]
    DIRECTION INPUT ;
    USE SIGNAL ;
    PORT
      LAYER met3 ;
        RECT 0.000000 62.440000 0.800000 62.740000 ;
    END
  END dwb_dat_i[17]
  PIN dwb_dat_i[16]
    DIRECTION INPUT ;
    USE SIGNAL ;
    PORT
      LAYER met3 ;
        RECT 0.000000 72.200000 0.800000 72.500000 ;
    END
  END dwb_dat_i[16]
  PIN dwb_dat_i[15]
    DIRECTION INPUT ;
    USE SIGNAL ;
    PORT
      LAYER met4 ;
        RECT 84.345000 0.000000 84.645000 0.800000 ;
    END
  END dwb_dat_i[15]
  PIN dwb_dat_i[14]
    DIRECTION INPUT ;
    USE SIGNAL ;
    PORT
      LAYER met2 ;
        RECT 63.050000 0.000000 63.190000 0.485000 ;
    END
  END dwb_dat_i[14]
  PIN dwb_dat_i[13]
    DIRECTION INPUT ;
    USE SIGNAL ;
    PORT
      LAYER met2 ;
        RECT 77.450000 0.000000 77.590000 0.485000 ;
    END
  END dwb_dat_i[13]
  PIN dwb_dat_i[12]
    DIRECTION INPUT ;
    USE SIGNAL ;
    PORT
      LAYER met5 ;
        RECT 0.000000 76.430000 2.500000 78.030000 ;
    END
  END dwb_dat_i[12]
  PIN dwb_dat_i[11]
    DIRECTION INPUT ;
    USE SIGNAL ;
    PORT
      LAYER met2 ;
        RECT 104.810000 0.000000 104.950000 0.485000 ;
    END
  END dwb_dat_i[11]
  PIN dwb_dat_i[10]
    DIRECTION INPUT ;
    USE SIGNAL ;
    PORT
      LAYER met3 ;
        RECT 0.000000 69.760000 0.800000 70.060000 ;
    END
  END dwb_dat_i[10]
  PIN dwb_dat_i[9]
    DIRECTION INPUT ;
    USE SIGNAL ;
    PORT
      LAYER met2 ;
        RECT 64.970000 0.000000 65.110000 0.485000 ;
    END
  END dwb_dat_i[9]
  PIN dwb_dat_i[8]
    DIRECTION INPUT ;
    USE SIGNAL ;
    PORT
      LAYER met4 ;
        RECT 73.275000 0.000000 73.575000 0.800000 ;
    END
  END dwb_dat_i[8]
  PIN dwb_dat_i[7]
    DIRECTION INPUT ;
    USE SIGNAL ;
    PORT
      LAYER met2 ;
        RECT 58.730000 0.000000 58.870000 0.485000 ;
    END
  END dwb_dat_i[7]
  PIN dwb_dat_i[6]
    DIRECTION INPUT ;
    USE SIGNAL ;
    PORT
      LAYER met5 ;
        RECT 0.000000 69.110000 2.500000 70.710000 ;
    END
  END dwb_dat_i[6]
  PIN dwb_dat_i[5]
    DIRECTION INPUT ;
    USE SIGNAL ;
    PORT
      LAYER met3 ;
        RECT 0.000000 73.420000 0.800000 73.720000 ;
    END
  END dwb_dat_i[5]
  PIN dwb_dat_i[4]
    DIRECTION INPUT ;
    USE SIGNAL ;
    PORT
      LAYER met4 ;
        RECT 49.905000 0.000000 50.205000 0.800000 ;
    END
  END dwb_dat_i[4]
  PIN dwb_dat_i[3]
    DIRECTION INPUT ;
    USE SIGNAL ;
    PORT
      LAYER met2 ;
        RECT 88.490000 0.000000 88.630000 0.485000 ;
    END
  END dwb_dat_i[3]
  PIN dwb_dat_i[2]
    DIRECTION INPUT ;
    USE SIGNAL ;
    PORT
      LAYER met3 ;
        RECT 0.000000 61.220000 0.800000 61.520000 ;
    END
  END dwb_dat_i[2]
  PIN dwb_dat_i[1]
    DIRECTION INPUT ;
    USE SIGNAL ;
    PORT
      LAYER met4 ;
        RECT 67.740000 0.000000 68.040000 0.800000 ;
    END
  END dwb_dat_i[1]
  PIN dwb_dat_i[0]
    DIRECTION INPUT ;
    USE SIGNAL ;
    PORT
      LAYER met3 ;
        RECT 0.000000 63.660000 0.800000 63.960000 ;
    END
  END dwb_dat_i[0]
  PIN dwb_we_i
    DIRECTION INPUT ;
    USE SIGNAL ;
    PORT
      LAYER met5 ;
        RECT 156.380000 47.150000 158.880000 48.750000 ;
    END
  END dwb_we_i
  PIN dwb_sel_i[3]
    DIRECTION INPUT ;
    USE SIGNAL ;
    PORT
      LAYER met2 ;
        RECT 78.410000 0.000000 78.550000 0.485000 ;
    END
  END dwb_sel_i[3]
  PIN dwb_sel_i[2]
    DIRECTION INPUT ;
    USE SIGNAL ;
    PORT
      LAYER met2 ;
        RECT 54.890000 0.000000 55.030000 0.485000 ;
    END
  END dwb_sel_i[2]
  PIN dwb_sel_i[1]
    DIRECTION INPUT ;
    USE SIGNAL ;
    PORT
      LAYER met3 ;
        RECT 0.000000 68.540000 0.800000 68.840000 ;
    END
  END dwb_sel_i[1]
  PIN dwb_sel_i[0]
    DIRECTION INPUT ;
    USE SIGNAL ;
    PORT
      LAYER met4 ;
        RECT 70.815000 0.000000 71.115000 0.800000 ;
    END
  END dwb_sel_i[0]
  PIN dwb_cyc_i
    DIRECTION INPUT ;
    USE SIGNAL ;
    PORT
      LAYER met2 ;
        RECT 112.010000 146.775000 112.150000 147.260000 ;
    END
  END dwb_cyc_i
  PIN dwb_stb_i
    DIRECTION INPUT ;
    USE SIGNAL ;
    PORT
      LAYER met4 ;
        RECT 112.020000 146.460000 112.320000 147.260000 ;
    END
  END dwb_stb_i
  PIN dwb_ack_o
    DIRECTION OUTPUT ;
    USE SIGNAL ;
    PORT
      LAYER met3 ;
        RECT 158.080000 100.870000 158.880000 101.170000 ;
    END
  END dwb_ack_o
  PIN dwb_err_o
    DIRECTION OUTPUT ;
    USE SIGNAL ;
    PORT
      LAYER met3 ;
        RECT 158.080000 97.210000 158.880000 97.510000 ;
    END
  END dwb_err_o
  PIN ext_mem_adr_o[31]
    DIRECTION OUTPUT ;
    USE SIGNAL ;
    PORT
      LAYER met2 ;
        RECT 80.810000 146.775000 80.950000 147.260000 ;
    END
  END ext_mem_adr_o[31]
  PIN ext_mem_adr_o[30]
    DIRECTION OUTPUT ;
    USE SIGNAL ;
    PORT
      LAYER met4 ;
        RECT 81.270000 0.000000 81.570000 0.800000 ;
    END
  END ext_mem_adr_o[30]
  PIN ext_mem_adr_o[29]
    DIRECTION OUTPUT ;
    USE SIGNAL ;
    PORT
      LAYER met3 ;
        RECT 158.080000 72.200000 158.880000 72.500000 ;
    END
  END ext_mem_adr_o[29]
  PIN ext_mem_adr_o[28]
    DIRECTION OUTPUT ;
    USE SIGNAL ;
    PORT
      LAYER met3 ;
        RECT 158.080000 74.640000 158.880000 74.940000 ;
    END
  END ext_mem_adr_o[28]
  PIN ext_mem_adr_o[27]
    DIRECTION OUTPUT ;
    USE SIGNAL ;
    PORT
      LAYER met4 ;
        RECT 78.195000 0.000000 78.495000 0.800000 ;
    END
  END ext_mem_adr_o[27]
  PIN ext_mem_adr_o[26]
    DIRECTION OUTPUT ;
    USE SIGNAL ;
    PORT
      LAYER met2 ;
        RECT 98.090000 0.000000 98.230000 0.485000 ;
    END
  END ext_mem_adr_o[26]
  PIN ext_mem_adr_o[25]
    DIRECTION OUTPUT ;
    USE SIGNAL ;
    PORT
      LAYER met2 ;
        RECT 85.610000 0.000000 85.750000 0.485000 ;
    END
  END ext_mem_adr_o[25]
  PIN ext_mem_adr_o[24]
    DIRECTION OUTPUT ;
    USE SIGNAL ;
    PORT
      LAYER met2 ;
        RECT 94.250000 0.000000 94.390000 0.485000 ;
    END
  END ext_mem_adr_o[24]
  PIN ext_mem_adr_o[23]
    DIRECTION OUTPUT ;
    USE SIGNAL ;
    PORT
      LAYER met3 ;
        RECT 158.080000 58.780000 158.880000 59.080000 ;
    END
  END ext_mem_adr_o[23]
  PIN ext_mem_adr_o[22]
    DIRECTION OUTPUT ;
    USE SIGNAL ;
    PORT
      LAYER met2 ;
        RECT 92.330000 0.000000 92.470000 0.485000 ;
    END
  END ext_mem_adr_o[22]
  PIN ext_mem_adr_o[21]
    DIRECTION OUTPUT ;
    USE SIGNAL ;
    PORT
      LAYER met3 ;
        RECT 158.080000 73.420000 158.880000 73.720000 ;
    END
  END ext_mem_adr_o[21]
  PIN ext_mem_adr_o[20]
    DIRECTION OUTPUT ;
    USE SIGNAL ;
    PORT
      LAYER met4 ;
        RECT 76.965000 0.000000 77.265000 0.800000 ;
    END
  END ext_mem_adr_o[20]
  PIN ext_mem_adr_o[19]
    DIRECTION OUTPUT ;
    USE SIGNAL ;
    PORT
      LAYER met3 ;
        RECT 158.080000 61.830000 158.880000 62.130000 ;
    END
  END ext_mem_adr_o[19]
  PIN ext_mem_adr_o[18]
    DIRECTION OUTPUT ;
    USE SIGNAL ;
    PORT
      LAYER met4 ;
        RECT 85.575000 0.000000 85.875000 0.800000 ;
    END
  END ext_mem_adr_o[18]
  PIN ext_mem_adr_o[17]
    DIRECTION OUTPUT ;
    USE SIGNAL ;
    PORT
      LAYER met5 ;
        RECT 156.380000 72.770000 158.880000 74.370000 ;
    END
  END ext_mem_adr_o[17]
  PIN ext_mem_adr_o[16]
    DIRECTION OUTPUT ;
    USE SIGNAL ;
    PORT
      LAYER met3 ;
        RECT 158.080000 60.610000 158.880000 60.910000 ;
    END
  END ext_mem_adr_o[16]
  PIN ext_mem_adr_o[15]
    DIRECTION OUTPUT ;
    USE SIGNAL ;
    PORT
      LAYER met4 ;
        RECT 97.875000 0.000000 98.175000 0.800000 ;
    END
  END ext_mem_adr_o[15]
  PIN ext_mem_adr_o[14]
    DIRECTION OUTPUT ;
    USE SIGNAL ;
    PORT
      LAYER met2 ;
        RECT 61.130000 0.000000 61.270000 0.485000 ;
    END
  END ext_mem_adr_o[14]
  PIN ext_mem_adr_o[13]
    DIRECTION OUTPUT ;
    USE SIGNAL ;
    PORT
      LAYER met2 ;
        RECT 76.490000 0.000000 76.630000 0.485000 ;
    END
  END ext_mem_adr_o[13]
  PIN ext_mem_adr_o[12]
    DIRECTION OUTPUT ;
    USE SIGNAL ;
    PORT
      LAYER met4 ;
        RECT 65.280000 0.000000 65.580000 0.800000 ;
    END
  END ext_mem_adr_o[12]
  PIN ext_mem_adr_o[11]
    DIRECTION OUTPUT ;
    USE SIGNAL ;
    PORT
      LAYER met2 ;
        RECT 74.090000 0.000000 74.230000 0.485000 ;
    END
  END ext_mem_adr_o[11]
  PIN ext_mem_adr_o[10]
    DIRECTION OUTPUT ;
    USE SIGNAL ;
    PORT
      LAYER met4 ;
        RECT 87.420000 0.000000 87.720000 0.800000 ;
    END
  END ext_mem_adr_o[10]
  PIN ext_mem_adr_o[9]
    DIRECTION OUTPUT ;
    USE SIGNAL ;
    PORT
      LAYER met2 ;
        RECT 49.130000 0.000000 49.270000 0.485000 ;
    END
  END ext_mem_adr_o[9]
  PIN ext_mem_adr_o[8]
    DIRECTION OUTPUT ;
    USE SIGNAL ;
    PORT
      LAYER met4 ;
        RECT 72.045000 146.460000 72.345000 147.260000 ;
    END
  END ext_mem_adr_o[8]
  PIN ext_mem_adr_o[7]
    DIRECTION OUTPUT ;
    USE SIGNAL ;
    PORT
      LAYER met2 ;
        RECT 110.090000 0.000000 110.230000 0.485000 ;
    END
  END ext_mem_adr_o[7]
  PIN ext_mem_adr_o[6]
    DIRECTION OUTPUT ;
    USE SIGNAL ;
    PORT
      LAYER met2 ;
        RECT 65.930000 0.000000 66.070000 0.485000 ;
    END
  END ext_mem_adr_o[6]
  PIN ext_mem_adr_o[5]
    DIRECTION OUTPUT ;
    USE SIGNAL ;
    PORT
      LAYER met4 ;
        RECT 68.970000 0.000000 69.270000 0.800000 ;
    END
  END ext_mem_adr_o[5]
  PIN ext_mem_adr_o[4]
    DIRECTION OUTPUT ;
    USE SIGNAL ;
    PORT
      LAYER met4 ;
        RECT 61.590000 0.000000 61.890000 0.800000 ;
    END
  END ext_mem_adr_o[4]
  PIN ext_mem_adr_o[3]
    DIRECTION OUTPUT ;
    USE SIGNAL ;
    PORT
      LAYER met2 ;
        RECT 97.130000 0.000000 97.270000 0.485000 ;
    END
  END ext_mem_adr_o[3]
  PIN ext_mem_adr_o[2]
    DIRECTION OUTPUT ;
    USE SIGNAL ;
    PORT
      LAYER met4 ;
        RECT 92.340000 0.000000 92.640000 0.800000 ;
    END
  END ext_mem_adr_o[2]
  PIN ext_mem_adr_o[1]
    DIRECTION OUTPUT ;
    USE SIGNAL ;
    PORT
      LAYER met3 ;
        RECT 0.000000 59.390000 0.800000 59.690000 ;
    END
  END ext_mem_adr_o[1]
  PIN ext_mem_adr_o[0]
    DIRECTION OUTPUT ;
    USE SIGNAL ;
    PORT
      LAYER met4 ;
        RECT 89.880000 0.000000 90.180000 0.800000 ;
    END
  END ext_mem_adr_o[0]
  PIN ext_mem_dat_o[31]
    DIRECTION OUTPUT ;
    USE SIGNAL ;
    PORT
      LAYER met4 ;
        RECT 72.045000 0.000000 72.345000 0.800000 ;
    END
  END ext_mem_dat_o[31]
  PIN ext_mem_dat_o[30]
    DIRECTION OUTPUT ;
    USE SIGNAL ;
    PORT
      LAYER met3 ;
        RECT 0.000000 56.950000 0.800000 57.250000 ;
    END
  END ext_mem_dat_o[30]
  PIN ext_mem_dat_o[29]
    DIRECTION OUTPUT ;
    USE SIGNAL ;
    PORT
      LAYER met3 ;
        RECT 0.000000 78.300000 0.800000 78.600000 ;
    END
  END ext_mem_dat_o[29]
  PIN ext_mem_dat_o[28]
    DIRECTION OUTPUT ;
    USE SIGNAL ;
    PORT
      LAYER met2 ;
        RECT 56.810000 0.000000 56.950000 0.485000 ;
    END
  END ext_mem_dat_o[28]
  PIN ext_mem_dat_o[27]
    DIRECTION OUTPUT ;
    USE SIGNAL ;
    PORT
      LAYER met3 ;
        RECT 0.000000 79.520000 0.800000 79.820000 ;
    END
  END ext_mem_dat_o[27]
  PIN ext_mem_dat_o[26]
    DIRECTION OUTPUT ;
    USE SIGNAL ;
    PORT
      LAYER met3 ;
        RECT 0.000000 67.320000 0.800000 67.620000 ;
    END
  END ext_mem_dat_o[26]
  PIN ext_mem_dat_o[25]
    DIRECTION OUTPUT ;
    USE SIGNAL ;
    PORT
      LAYER met2 ;
        RECT 90.410000 0.000000 90.550000 0.485000 ;
    END
  END ext_mem_dat_o[25]
  PIN ext_mem_dat_o[24]
    DIRECTION OUTPUT ;
    USE SIGNAL ;
    PORT
      LAYER met2 ;
        RECT 101.930000 0.000000 102.070000 0.485000 ;
    END
  END ext_mem_dat_o[24]
  PIN ext_mem_dat_o[23]
    DIRECTION OUTPUT ;
    USE SIGNAL ;
    PORT
      LAYER met4 ;
        RECT 84.345000 146.460000 84.645000 147.260000 ;
    END
  END ext_mem_dat_o[23]
  PIN ext_mem_dat_o[22]
    DIRECTION OUTPUT ;
    USE SIGNAL ;
    PORT
      LAYER met4 ;
        RECT 66.510000 0.000000 66.810000 0.800000 ;
    END
  END ext_mem_dat_o[22]
  PIN ext_mem_dat_o[21]
    DIRECTION OUTPUT ;
    USE SIGNAL ;
    PORT
      LAYER met3 ;
        RECT 0.000000 66.100000 0.800000 66.400000 ;
    END
  END ext_mem_dat_o[21]
  PIN ext_mem_dat_o[20]
    DIRECTION OUTPUT ;
    USE SIGNAL ;
    PORT
      LAYER met3 ;
        RECT 0.000000 64.880000 0.800000 65.180000 ;
    END
  END ext_mem_dat_o[20]
  PIN ext_mem_dat_o[19]
    DIRECTION OUTPUT ;
    USE SIGNAL ;
    PORT
      LAYER met3 ;
        RECT 0.000000 92.330000 0.800000 92.630000 ;
    END
  END ext_mem_dat_o[19]
  PIN ext_mem_dat_o[18]
    DIRECTION OUTPUT ;
    USE SIGNAL ;
    PORT
      LAYER met4 ;
        RECT 100.950000 0.000000 101.250000 0.800000 ;
    END
  END ext_mem_dat_o[18]
  PIN ext_mem_dat_o[17]
    DIRECTION OUTPUT ;
    USE SIGNAL ;
    PORT
      LAYER met4 ;
        RECT 62.820000 0.000000 63.120000 0.800000 ;
    END
  END ext_mem_dat_o[17]
  PIN ext_mem_dat_o[16]
    DIRECTION OUTPUT ;
    USE SIGNAL ;
    PORT
      LAYER met4 ;
        RECT 59.130000 0.000000 59.430000 0.800000 ;
    END
  END ext_mem_dat_o[16]
  PIN ext_mem_dat_o[15]
    DIRECTION OUTPUT ;
    USE SIGNAL ;
    PORT
      LAYER met2 ;
        RECT 93.290000 0.000000 93.430000 0.485000 ;
    END
  END ext_mem_dat_o[15]
  PIN ext_mem_dat_o[14]
    DIRECTION OUTPUT ;
    USE SIGNAL ;
    PORT
      LAYER met4 ;
        RECT 64.050000 0.000000 64.350000 0.800000 ;
    END
  END ext_mem_dat_o[14]
  PIN ext_mem_dat_o[13]
    DIRECTION OUTPUT ;
    USE SIGNAL ;
    PORT
      LAYER met2 ;
        RECT 62.090000 0.000000 62.230000 0.485000 ;
    END
  END ext_mem_dat_o[13]
  PIN ext_mem_dat_o[12]
    DIRECTION OUTPUT ;
    USE SIGNAL ;
    PORT
      LAYER met4 ;
        RECT 56.055000 146.460000 56.355000 147.260000 ;
    END
  END ext_mem_dat_o[12]
  PIN ext_mem_dat_o[11]
    DIRECTION OUTPUT ;
    USE SIGNAL ;
    PORT
      LAYER met2 ;
        RECT 105.770000 0.000000 105.910000 0.485000 ;
    END
  END ext_mem_dat_o[11]
  PIN ext_mem_dat_o[10]
    DIRECTION OUTPUT ;
    USE SIGNAL ;
    PORT
      LAYER met2 ;
        RECT 57.770000 0.000000 57.910000 0.485000 ;
    END
  END ext_mem_dat_o[10]
  PIN ext_mem_dat_o[9]
    DIRECTION OUTPUT ;
    USE SIGNAL ;
    PORT
      LAYER met4 ;
        RECT 57.900000 0.000000 58.200000 0.800000 ;
    END
  END ext_mem_dat_o[9]
  PIN ext_mem_dat_o[8]
    DIRECTION OUTPUT ;
    USE SIGNAL ;
    PORT
      LAYER met4 ;
        RECT 56.670000 0.000000 56.970000 0.800000 ;
    END
  END ext_mem_dat_o[8]
  PIN ext_mem_dat_o[7]
    DIRECTION OUTPUT ;
    USE SIGNAL ;
    PORT
      LAYER met4 ;
        RECT 55.440000 0.000000 55.740000 0.800000 ;
    END
  END ext_mem_dat_o[7]
  PIN ext_mem_dat_o[6]
    DIRECTION OUTPUT ;
    USE SIGNAL ;
    PORT
      LAYER met3 ;
        RECT 0.000000 55.730000 0.800000 56.030000 ;
    END
  END ext_mem_dat_o[6]
  PIN ext_mem_dat_o[5]
    DIRECTION OUTPUT ;
    USE SIGNAL ;
    PORT
      LAYER met2 ;
        RECT 55.850000 146.775000 55.990000 147.260000 ;
    END
  END ext_mem_dat_o[5]
  PIN ext_mem_dat_o[4]
    DIRECTION OUTPUT ;
    USE SIGNAL ;
    PORT
      LAYER met2 ;
        RECT 52.490000 0.000000 52.630000 0.485000 ;
    END
  END ext_mem_dat_o[4]
  PIN ext_mem_dat_o[3]
    DIRECTION OUTPUT ;
    USE SIGNAL ;
    PORT
      LAYER met4 ;
        RECT 93.570000 0.000000 93.870000 0.800000 ;
    END
  END ext_mem_dat_o[3]
  PIN ext_mem_dat_o[2]
    DIRECTION OUTPUT ;
    USE SIGNAL ;
    PORT
      LAYER met3 ;
        RECT 0.000000 54.510000 0.800000 54.810000 ;
    END
  END ext_mem_dat_o[2]
  PIN ext_mem_dat_o[1]
    DIRECTION OUTPUT ;
    USE SIGNAL ;
    PORT
      LAYER met4 ;
        RECT 54.210000 0.000000 54.510000 0.800000 ;
    END
  END ext_mem_dat_o[1]
  PIN ext_mem_dat_o[0]
    DIRECTION OUTPUT ;
    USE SIGNAL ;
    PORT
      LAYER met3 ;
        RECT 0.000000 53.290000 0.800000 53.590000 ;
    END
  END ext_mem_dat_o[0]
  PIN ext_mem_dat_i[31]
    DIRECTION INPUT ;
    USE SIGNAL ;
    PORT
      LAYER met2 ;
        RECT 75.530000 146.775000 75.670000 147.260000 ;
    END
  END ext_mem_dat_i[31]
  PIN ext_mem_dat_i[30]
    DIRECTION INPUT ;
    USE SIGNAL ;
    PORT
      LAYER met2 ;
        RECT 69.770000 146.775000 69.910000 147.260000 ;
    END
  END ext_mem_dat_i[30]
  PIN ext_mem_dat_i[29]
    DIRECTION INPUT ;
    USE SIGNAL ;
    PORT
      LAYER met4 ;
        RECT 58.515000 146.460000 58.815000 147.260000 ;
    END
  END ext_mem_dat_i[29]
  PIN ext_mem_dat_i[28]
    DIRECTION INPUT ;
    USE SIGNAL ;
    PORT
      LAYER met3 ;
        RECT 0.000000 83.180000 0.800000 83.480000 ;
    END
  END ext_mem_dat_i[28]
  PIN ext_mem_dat_i[27]
    DIRECTION INPUT ;
    USE SIGNAL ;
    PORT
      LAYER met4 ;
        RECT 80.655000 146.460000 80.955000 147.260000 ;
    END
  END ext_mem_dat_i[27]
  PIN ext_mem_dat_i[26]
    DIRECTION INPUT ;
    USE SIGNAL ;
    PORT
      LAYER met2 ;
        RECT 74.570000 146.775000 74.710000 147.260000 ;
    END
  END ext_mem_dat_i[26]
  PIN ext_mem_dat_i[25]
    DIRECTION INPUT ;
    USE SIGNAL ;
    PORT
      LAYER met4 ;
        RECT 64.050000 146.460000 64.350000 147.260000 ;
    END
  END ext_mem_dat_i[25]
  PIN ext_mem_dat_i[24]
    DIRECTION INPUT ;
    USE SIGNAL ;
    PORT
      LAYER met4 ;
        RECT 74.505000 146.460000 74.805000 147.260000 ;
    END
  END ext_mem_dat_i[24]
  PIN ext_mem_dat_i[23]
    DIRECTION INPUT ;
    USE SIGNAL ;
    PORT
      LAYER met2 ;
        RECT 90.410000 146.775000 90.550000 147.260000 ;
    END
  END ext_mem_dat_i[23]
  PIN ext_mem_dat_i[22]
    DIRECTION INPUT ;
    USE SIGNAL ;
    PORT
      LAYER met2 ;
        RECT 82.730000 146.775000 82.870000 147.260000 ;
    END
  END ext_mem_dat_i[22]
  PIN ext_mem_dat_i[21]
    DIRECTION INPUT ;
    USE SIGNAL ;
    PORT
      LAYER met2 ;
        RECT 54.410000 146.775000 54.550000 147.260000 ;
    END
  END ext_mem_dat_i[21]
  PIN ext_mem_dat_i[20]
    DIRECTION INPUT ;
    USE SIGNAL ;
    PORT
      LAYER met4 ;
        RECT 60.975000 146.460000 61.275000 147.260000 ;
    END
  END ext_mem_dat_i[20]
  PIN ext_mem_dat_i[19]
    DIRECTION INPUT ;
    USE SIGNAL ;
    PORT
      LAYER met2 ;
        RECT 89.450000 146.775000 89.590000 147.260000 ;
    END
  END ext_mem_dat_i[19]
  PIN ext_mem_dat_i[18]
    DIRECTION INPUT ;
    USE SIGNAL ;
    PORT
      LAYER met2 ;
        RECT 65.450000 146.775000 65.590000 147.260000 ;
    END
  END ext_mem_dat_i[18]
  PIN ext_mem_dat_i[17]
    DIRECTION INPUT ;
    USE SIGNAL ;
    PORT
      LAYER met4 ;
        RECT 57.285000 146.460000 57.585000 147.260000 ;
    END
  END ext_mem_dat_i[17]
  PIN ext_mem_dat_i[16]
    DIRECTION INPUT ;
    USE SIGNAL ;
    PORT
      LAYER met2 ;
        RECT 71.210000 146.775000 71.350000 147.260000 ;
    END
  END ext_mem_dat_i[16]
  PIN ext_mem_dat_i[15]
    DIRECTION INPUT ;
    USE SIGNAL ;
    PORT
      LAYER met3 ;
        RECT 0.000000 81.960000 0.800000 82.260000 ;
    END
  END ext_mem_dat_i[15]
  PIN ext_mem_dat_i[14]
    DIRECTION INPUT ;
    USE SIGNAL ;
    PORT
      LAYER met4 ;
        RECT 70.815000 146.460000 71.115000 147.260000 ;
    END
  END ext_mem_dat_i[14]
  PIN ext_mem_dat_i[13]
    DIRECTION INPUT ;
    USE SIGNAL ;
    PORT
      LAYER met2 ;
        RECT 64.490000 146.775000 64.630000 147.260000 ;
    END
  END ext_mem_dat_i[13]
  PIN ext_mem_dat_i[12]
    DIRECTION INPUT ;
    USE SIGNAL ;
    PORT
      LAYER met3 ;
        RECT 0.000000 86.840000 0.800000 87.140000 ;
    END
  END ext_mem_dat_i[12]
  PIN ext_mem_dat_i[11]
    DIRECTION INPUT ;
    USE SIGNAL ;
    PORT
      LAYER met2 ;
        RECT 83.690000 146.775000 83.830000 147.260000 ;
    END
  END ext_mem_dat_i[11]
  PIN ext_mem_dat_i[10]
    DIRECTION INPUT ;
    USE SIGNAL ;
    PORT
      LAYER met2 ;
        RECT 59.690000 146.775000 59.830000 147.260000 ;
    END
  END ext_mem_dat_i[10]
  PIN ext_mem_dat_i[9]
    DIRECTION INPUT ;
    USE SIGNAL ;
    PORT
      LAYER met4 ;
        RECT 59.745000 146.460000 60.045000 147.260000 ;
    END
  END ext_mem_dat_i[9]
  PIN ext_mem_dat_i[8]
    DIRECTION INPUT ;
    USE SIGNAL ;
    PORT
      LAYER met3 ;
        RECT 0.000000 89.890000 0.800000 90.190000 ;
    END
  END ext_mem_dat_i[8]
  PIN ext_mem_dat_i[7]
    DIRECTION INPUT ;
    USE SIGNAL ;
    PORT
      LAYER met2 ;
        RECT 93.770000 146.775000 93.910000 147.260000 ;
    END
  END ext_mem_dat_i[7]
  PIN ext_mem_dat_i[6]
    DIRECTION INPUT ;
    USE SIGNAL ;
    PORT
      LAYER met2 ;
        RECT 56.810000 146.775000 56.950000 147.260000 ;
    END
  END ext_mem_dat_i[6]
  PIN ext_mem_dat_i[5]
    DIRECTION INPUT ;
    USE SIGNAL ;
    PORT
      LAYER met3 ;
        RECT 0.000000 91.110000 0.800000 91.410000 ;
    END
  END ext_mem_dat_i[5]
  PIN ext_mem_dat_i[4]
    DIRECTION INPUT ;
    USE SIGNAL ;
    PORT
      LAYER met2 ;
        RECT 84.650000 146.775000 84.790000 147.260000 ;
    END
  END ext_mem_dat_i[4]
  PIN ext_mem_dat_i[3]
    DIRECTION INPUT ;
    USE SIGNAL ;
    PORT
      LAYER met3 ;
        RECT 0.000000 80.740000 0.800000 81.040000 ;
    END
  END ext_mem_dat_i[3]
  PIN ext_mem_dat_i[2]
    DIRECTION INPUT ;
    USE SIGNAL ;
    PORT
      LAYER met4 ;
        RECT 54.825000 146.460000 55.125000 147.260000 ;
    END
  END ext_mem_dat_i[2]
  PIN ext_mem_dat_i[1]
    DIRECTION INPUT ;
    USE SIGNAL ;
    PORT
      LAYER met4 ;
        RECT 86.805000 146.460000 87.105000 147.260000 ;
    END
  END ext_mem_dat_i[1]
  PIN ext_mem_dat_i[0]
    DIRECTION INPUT ;
    USE SIGNAL ;
    PORT
      LAYER met4 ;
        RECT 83.115000 146.460000 83.415000 147.260000 ;
    END
  END ext_mem_dat_i[0]
  PIN ext_mem_we_o
    DIRECTION OUTPUT ;
    USE SIGNAL ;
    PORT
      LAYER met3 ;
        RECT 158.080000 46.580000 158.880000 46.880000 ;
    END
  END ext_mem_we_o
  PIN ext_mem_sel_o[3]
    DIRECTION OUTPUT ;
    USE SIGNAL ;
    PORT
      LAYER met4 ;
        RECT 94.800000 0.000000 95.100000 0.800000 ;
    END
  END ext_mem_sel_o[3]
  PIN ext_mem_sel_o[2]
    DIRECTION OUTPUT ;
    USE SIGNAL ;
    PORT
      LAYER met2 ;
        RECT 53.930000 0.000000 54.070000 0.485000 ;
    END
  END ext_mem_sel_o[2]
  PIN ext_mem_sel_o[1]
    DIRECTION OUTPUT ;
    USE SIGNAL ;
    PORT
      LAYER met3 ;
        RECT 0.000000 52.070000 0.800000 52.370000 ;
    END
  END ext_mem_sel_o[1]
  PIN ext_mem_sel_o[0]
    DIRECTION OUTPUT ;
    USE SIGNAL ;
    PORT
      LAYER met4 ;
        RECT 52.980000 0.000000 53.280000 0.800000 ;
    END
  END ext_mem_sel_o[0]
  PIN ext_mem_cyc_o
    DIRECTION OUTPUT ;
    USE SIGNAL ;
    PORT
      LAYER met2 ;
        RECT 110.090000 146.775000 110.230000 147.260000 ;
    END
  END ext_mem_cyc_o
  PIN ext_mem_stb_o
    DIRECTION OUTPUT ;
    USE SIGNAL ;
    PORT
      LAYER met2 ;
        RECT 109.130000 146.775000 109.270000 147.260000 ;
    END
  END ext_mem_stb_o
  PIN ext_mem_ack_i
    DIRECTION INPUT ;
    USE SIGNAL ;
    PORT
      LAYER met3 ;
        RECT 158.080000 85.010000 158.880000 85.310000 ;
    END
  END ext_mem_ack_i
  PIN ext_mem_err_i
    DIRECTION INPUT ;
    USE SIGNAL ;
    PORT
      LAYER met2 ;
        RECT 112.970000 146.775000 113.110000 147.260000 ;
    END
  END ext_mem_err_i
  PIN rom_ready
    DIRECTION OUTPUT ;
    USE SIGNAL ;
    PORT
      LAYER met4 ;
        RECT 112.020000 0.000000 112.320000 0.800000 ;
    END
  END rom_ready
  PIN ram_ready
    DIRECTION OUTPUT ;
    USE SIGNAL ;
    PORT
      LAYER met2 ;
        RECT 112.970000 0.000000 113.110000 0.485000 ;
    END
  END ram_ready
  PIN memory_status[31]
    DIRECTION OUTPUT ;
    USE SIGNAL ;
    PORT
      LAYER met3 ;
        RECT 158.080000 80.740000 158.880000 81.040000 ;
    END
  END memory_status[31]
  PIN memory_status[30]
    DIRECTION OUTPUT ;
    USE SIGNAL ;
    PORT
      LAYER met5 ;
        RECT 156.380000 80.090000 158.880000 81.690000 ;
    END
  END memory_status[30]
  PIN memory_status[29]
    DIRECTION OUTPUT ;
    USE SIGNAL ;
    PORT
      LAYER met3 ;
        RECT 158.080000 86.230000 158.880000 86.530000 ;
    END
  END memory_status[29]
  PIN memory_status[28]
    DIRECTION OUTPUT ;
    USE SIGNAL ;
    PORT
      LAYER met3 ;
        RECT 158.080000 87.450000 158.880000 87.750000 ;
    END
  END memory_status[28]
  PIN memory_status[27]
    DIRECTION OUTPUT ;
    USE SIGNAL ;
    PORT
      LAYER met5 ;
        RECT 156.380000 87.410000 158.880000 89.010000 ;
    END
  END memory_status[27]
  PIN memory_status[26]
    DIRECTION OUTPUT ;
    USE SIGNAL ;
    PORT
      LAYER met4 ;
        RECT 99.720000 146.460000 100.020000 147.260000 ;
    END
  END memory_status[26]
  PIN memory_status[25]
    DIRECTION OUTPUT ;
    USE SIGNAL ;
    PORT
      LAYER met3 ;
        RECT 158.080000 88.670000 158.880000 88.970000 ;
    END
  END memory_status[25]
  PIN memory_status[24]
    DIRECTION OUTPUT ;
    USE SIGNAL ;
    PORT
      LAYER met2 ;
        RECT 100.490000 146.775000 100.630000 147.260000 ;
    END
  END memory_status[24]
  PIN memory_status[23]
    DIRECTION OUTPUT ;
    USE SIGNAL ;
    PORT
      LAYER met4 ;
        RECT 100.950000 146.460000 101.250000 147.260000 ;
    END
  END memory_status[23]
  PIN memory_status[22]
    DIRECTION OUTPUT ;
    USE SIGNAL ;
    PORT
      LAYER met2 ;
        RECT 101.450000 146.775000 101.590000 147.260000 ;
    END
  END memory_status[22]
  PIN memory_status[21]
    DIRECTION OUTPUT ;
    USE SIGNAL ;
    PORT
      LAYER met3 ;
        RECT 158.080000 89.890000 158.880000 90.190000 ;
    END
  END memory_status[21]
  PIN memory_status[20]
    DIRECTION OUTPUT ;
    USE SIGNAL ;
    PORT
      LAYER met4 ;
        RECT 102.180000 146.460000 102.480000 147.260000 ;
    END
  END memory_status[20]
  PIN memory_status[19]
    DIRECTION OUTPUT ;
    USE SIGNAL ;
    PORT
      LAYER met3 ;
        RECT 158.080000 91.110000 158.880000 91.410000 ;
    END
  END memory_status[19]
  PIN memory_status[18]
    DIRECTION OUTPUT ;
    USE SIGNAL ;
    PORT
      LAYER met2 ;
        RECT 103.370000 146.775000 103.510000 147.260000 ;
    END
  END memory_status[18]
  PIN memory_status[17]
    DIRECTION OUTPUT ;
    USE SIGNAL ;
    PORT
      LAYER met4 ;
        RECT 103.410000 146.460000 103.710000 147.260000 ;
    END
  END memory_status[17]
  PIN memory_status[16]
    DIRECTION OUTPUT ;
    USE SIGNAL ;
    PORT
      LAYER met3 ;
        RECT 158.080000 92.330000 158.880000 92.630000 ;
    END
  END memory_status[16]
  PIN memory_status[15]
    DIRECTION OUTPUT ;
    USE SIGNAL ;
    PORT
      LAYER met2 ;
        RECT 104.330000 146.775000 104.470000 147.260000 ;
    END
  END memory_status[15]
  PIN memory_status[14]
    DIRECTION OUTPUT ;
    USE SIGNAL ;
    PORT
      LAYER met4 ;
        RECT 104.640000 146.460000 104.940000 147.260000 ;
    END
  END memory_status[14]
  PIN memory_status[13]
    DIRECTION OUTPUT ;
    USE SIGNAL ;
    PORT
      LAYER met3 ;
        RECT 158.080000 53.900000 158.880000 54.200000 ;
    END
  END memory_status[13]
  PIN memory_status[12]
    DIRECTION OUTPUT ;
    USE SIGNAL ;
    PORT
      LAYER met3 ;
        RECT 158.080000 83.790000 158.880000 84.090000 ;
    END
  END memory_status[12]
  PIN memory_status[11]
    DIRECTION OUTPUT ;
    USE SIGNAL ;
    PORT
      LAYER met3 ;
        RECT 158.080000 93.550000 158.880000 93.850000 ;
    END
  END memory_status[11]
  PIN memory_status[10]
    DIRECTION OUTPUT ;
    USE SIGNAL ;
    PORT
      LAYER met2 ;
        RECT 105.290000 146.775000 105.430000 147.260000 ;
    END
  END memory_status[10]
  PIN memory_status[9]
    DIRECTION OUTPUT ;
    USE SIGNAL ;
    PORT
      LAYER met4 ;
        RECT 105.870000 146.460000 106.170000 147.260000 ;
    END
  END memory_status[9]
  PIN memory_status[8]
    DIRECTION OUTPUT ;
    USE SIGNAL ;
    PORT
      LAYER met3 ;
        RECT 158.080000 52.680000 158.880000 52.980000 ;
    END
  END memory_status[8]
  PIN memory_status[7]
    DIRECTION OUTPUT ;
    USE SIGNAL ;
    PORT
      LAYER met2 ;
        RECT 106.250000 146.775000 106.390000 147.260000 ;
    END
  END memory_status[7]
  PIN memory_status[6]
    DIRECTION OUTPUT ;
    USE SIGNAL ;
    PORT
      LAYER met3 ;
        RECT 158.080000 94.770000 158.880000 95.070000 ;
    END
  END memory_status[6]
  PIN memory_status[5]
    DIRECTION OUTPUT ;
    USE SIGNAL ;
    PORT
      LAYER met5 ;
        RECT 156.380000 94.730000 158.880000 96.330000 ;
    END
  END memory_status[5]
  PIN memory_status[4]
    DIRECTION OUTPUT ;
    USE SIGNAL ;
    PORT
      LAYER met2 ;
        RECT 107.210000 146.775000 107.350000 147.260000 ;
    END
  END memory_status[4]
  PIN memory_status[3]
    DIRECTION OUTPUT ;
    USE SIGNAL ;
    PORT
      LAYER met4 ;
        RECT 107.100000 146.460000 107.400000 147.260000 ;
    END
  END memory_status[3]
  PIN memory_status[2]
    DIRECTION OUTPUT ;
    USE SIGNAL ;
    PORT
      LAYER met3 ;
        RECT 158.080000 95.990000 158.880000 96.290000 ;
    END
  END memory_status[2]
  PIN memory_status[1]
    DIRECTION OUTPUT ;
    USE SIGNAL ;
    PORT
      LAYER met2 ;
        RECT 108.170000 146.775000 108.310000 147.260000 ;
    END
  END memory_status[1]
  PIN memory_status[0]
    DIRECTION OUTPUT ;
    USE SIGNAL ;
    PORT
      LAYER met4 ;
        RECT 108.330000 146.460000 108.630000 147.260000 ;
    END
  END memory_status[0]
  OBS
    LAYER met1 ;
      RECT 0.000000 0.000000 158.880000 147.260000 ;
    LAYER met2 ;
      RECT 113.250000 146.635000 158.880000 147.260000 ;
      RECT 112.290000 146.635000 112.830000 147.260000 ;
      RECT 111.330000 146.635000 111.870000 147.260000 ;
      RECT 110.370000 146.635000 110.910000 147.260000 ;
      RECT 109.410000 146.635000 109.950000 147.260000 ;
      RECT 108.450000 146.635000 108.990000 147.260000 ;
      RECT 107.490000 146.635000 108.030000 147.260000 ;
      RECT 106.530000 146.635000 107.070000 147.260000 ;
      RECT 105.570000 146.635000 106.110000 147.260000 ;
      RECT 104.610000 146.635000 105.150000 147.260000 ;
      RECT 103.650000 146.635000 104.190000 147.260000 ;
      RECT 102.690000 146.635000 103.230000 147.260000 ;
      RECT 101.730000 146.635000 102.270000 147.260000 ;
      RECT 100.770000 146.635000 101.310000 147.260000 ;
      RECT 99.810000 146.635000 100.350000 147.260000 ;
      RECT 98.850000 146.635000 99.390000 147.260000 ;
      RECT 97.890000 146.635000 98.430000 147.260000 ;
      RECT 96.930000 146.635000 97.470000 147.260000 ;
      RECT 95.970000 146.635000 96.510000 147.260000 ;
      RECT 95.010000 146.635000 95.550000 147.260000 ;
      RECT 94.050000 146.635000 94.590000 147.260000 ;
      RECT 92.610000 146.635000 93.630000 147.260000 ;
      RECT 91.650000 146.635000 92.190000 147.260000 ;
      RECT 90.690000 146.635000 91.230000 147.260000 ;
      RECT 89.730000 146.635000 90.270000 147.260000 ;
      RECT 88.770000 146.635000 89.310000 147.260000 ;
      RECT 87.330000 146.635000 88.350000 147.260000 ;
      RECT 85.890000 146.635000 86.910000 147.260000 ;
      RECT 84.930000 146.635000 85.470000 147.260000 ;
      RECT 83.970000 146.635000 84.510000 147.260000 ;
      RECT 83.010000 146.635000 83.550000 147.260000 ;
      RECT 82.050000 146.635000 82.590000 147.260000 ;
      RECT 81.090000 146.635000 81.630000 147.260000 ;
      RECT 80.130000 146.635000 80.670000 147.260000 ;
      RECT 79.170000 146.635000 79.710000 147.260000 ;
      RECT 77.730000 146.635000 78.750000 147.260000 ;
      RECT 76.770000 146.635000 77.310000 147.260000 ;
      RECT 75.810000 146.635000 76.350000 147.260000 ;
      RECT 74.850000 146.635000 75.390000 147.260000 ;
      RECT 73.410000 146.635000 74.430000 147.260000 ;
      RECT 72.450000 146.635000 72.990000 147.260000 ;
      RECT 71.490000 146.635000 72.030000 147.260000 ;
      RECT 70.050000 146.635000 71.070000 147.260000 ;
      RECT 69.090000 146.635000 69.630000 147.260000 ;
      RECT 67.650000 146.635000 68.670000 147.260000 ;
      RECT 66.690000 146.635000 67.230000 147.260000 ;
      RECT 65.730000 146.635000 66.270000 147.260000 ;
      RECT 64.770000 146.635000 65.310000 147.260000 ;
      RECT 63.810000 146.635000 64.350000 147.260000 ;
      RECT 62.370000 146.635000 63.390000 147.260000 ;
      RECT 60.930000 146.635000 61.950000 147.260000 ;
      RECT 59.970000 146.635000 60.510000 147.260000 ;
      RECT 59.010000 146.635000 59.550000 147.260000 ;
      RECT 58.050000 146.635000 58.590000 147.260000 ;
      RECT 57.090000 146.635000 57.630000 147.260000 ;
      RECT 56.130000 146.635000 56.670000 147.260000 ;
      RECT 54.690000 146.635000 55.710000 147.260000 ;
      RECT 53.730000 146.635000 54.270000 147.260000 ;
      RECT 52.770000 146.635000 53.310000 147.260000 ;
      RECT 51.810000 146.635000 52.350000 147.260000 ;
      RECT 50.850000 146.635000 51.390000 147.260000 ;
      RECT 49.890000 146.635000 50.430000 147.260000 ;
      RECT 48.930000 146.635000 49.470000 147.260000 ;
      RECT 47.970000 146.635000 48.510000 147.260000 ;
      RECT 47.010000 146.635000 47.550000 147.260000 ;
      RECT 46.050000 146.635000 46.590000 147.260000 ;
      RECT 45.090000 146.635000 45.630000 147.260000 ;
      RECT 44.130000 146.635000 44.670000 147.260000 ;
      RECT 0.000000 146.635000 43.710000 147.260000 ;
      RECT 0.000000 0.625000 158.880000 146.635000 ;
      RECT 113.250000 0.000000 158.880000 0.625000 ;
      RECT 112.290000 0.000000 112.830000 0.625000 ;
      RECT 111.330000 0.000000 111.870000 0.625000 ;
      RECT 110.370000 0.000000 110.910000 0.625000 ;
      RECT 108.930000 0.000000 109.950000 0.625000 ;
      RECT 107.970000 0.000000 108.510000 0.625000 ;
      RECT 107.010000 0.000000 107.550000 0.625000 ;
      RECT 106.050000 0.000000 106.590000 0.625000 ;
      RECT 105.090000 0.000000 105.630000 0.625000 ;
      RECT 104.130000 0.000000 104.670000 0.625000 ;
      RECT 103.170000 0.000000 103.710000 0.625000 ;
      RECT 102.210000 0.000000 102.750000 0.625000 ;
      RECT 100.770000 0.000000 101.790000 0.625000 ;
      RECT 99.810000 0.000000 100.350000 0.625000 ;
      RECT 98.370000 0.000000 99.390000 0.625000 ;
      RECT 97.410000 0.000000 97.950000 0.625000 ;
      RECT 95.970000 0.000000 96.990000 0.625000 ;
      RECT 94.530000 0.000000 95.550000 0.625000 ;
      RECT 93.570000 0.000000 94.110000 0.625000 ;
      RECT 92.610000 0.000000 93.150000 0.625000 ;
      RECT 91.650000 0.000000 92.190000 0.625000 ;
      RECT 90.690000 0.000000 91.230000 0.625000 ;
      RECT 89.730000 0.000000 90.270000 0.625000 ;
      RECT 88.770000 0.000000 89.310000 0.625000 ;
      RECT 87.330000 0.000000 88.350000 0.625000 ;
      RECT 85.890000 0.000000 86.910000 0.625000 ;
      RECT 84.450000 0.000000 85.470000 0.625000 ;
      RECT 83.010000 0.000000 84.030000 0.625000 ;
      RECT 81.570000 0.000000 82.590000 0.625000 ;
      RECT 80.130000 0.000000 81.150000 0.625000 ;
      RECT 78.690000 0.000000 79.710000 0.625000 ;
      RECT 77.730000 0.000000 78.270000 0.625000 ;
      RECT 76.770000 0.000000 77.310000 0.625000 ;
      RECT 75.810000 0.000000 76.350000 0.625000 ;
      RECT 74.370000 0.000000 75.390000 0.625000 ;
      RECT 73.410000 0.000000 73.950000 0.625000 ;
      RECT 72.450000 0.000000 72.990000 0.625000 ;
      RECT 71.010000 0.000000 72.030000 0.625000 ;
      RECT 69.570000 0.000000 70.590000 0.625000 ;
      RECT 68.610000 0.000000 69.150000 0.625000 ;
      RECT 67.170000 0.000000 68.190000 0.625000 ;
      RECT 66.210000 0.000000 66.750000 0.625000 ;
      RECT 65.250000 0.000000 65.790000 0.625000 ;
      RECT 64.290000 0.000000 64.830000 0.625000 ;
      RECT 63.330000 0.000000 63.870000 0.625000 ;
      RECT 62.370000 0.000000 62.910000 0.625000 ;
      RECT 61.410000 0.000000 61.950000 0.625000 ;
      RECT 60.450000 0.000000 60.990000 0.625000 ;
      RECT 59.010000 0.000000 60.030000 0.625000 ;
      RECT 58.050000 0.000000 58.590000 0.625000 ;
      RECT 57.090000 0.000000 57.630000 0.625000 ;
      RECT 56.130000 0.000000 56.670000 0.625000 ;
      RECT 55.170000 0.000000 55.710000 0.625000 ;
      RECT 54.210000 0.000000 54.750000 0.625000 ;
      RECT 52.770000 0.000000 53.790000 0.625000 ;
      RECT 51.810000 0.000000 52.350000 0.625000 ;
      RECT 50.850000 0.000000 51.390000 0.625000 ;
      RECT 49.410000 0.000000 50.430000 0.625000 ;
      RECT 48.450000 0.000000 48.990000 0.625000 ;
      RECT 47.490000 0.000000 48.030000 0.625000 ;
      RECT 46.530000 0.000000 47.070000 0.625000 ;
      RECT 45.570000 0.000000 46.110000 0.625000 ;
      RECT 44.610000 0.000000 45.150000 0.625000 ;
      RECT 43.650000 0.000000 44.190000 0.625000 ;
      RECT 42.690000 0.000000 43.230000 0.625000 ;
      RECT 41.730000 0.000000 42.270000 0.625000 ;
      RECT 40.770000 0.000000 41.310000 0.625000 ;
      RECT 0.000000 0.000000 40.350000 0.625000 ;
    LAYER met3 ;
      RECT 0.000000 102.690000 158.880000 147.260000 ;
      RECT 1.100000 101.790000 158.880000 102.690000 ;
      RECT 0.000000 101.470000 158.880000 101.790000 ;
      RECT 1.100000 100.570000 157.780000 101.470000 ;
      RECT 0.000000 100.250000 158.880000 100.570000 ;
      RECT 1.100000 99.350000 157.780000 100.250000 ;
      RECT 0.000000 99.030000 158.880000 99.350000 ;
      RECT 1.100000 98.130000 157.780000 99.030000 ;
      RECT 0.000000 97.810000 158.880000 98.130000 ;
      RECT 1.100000 96.910000 157.780000 97.810000 ;
      RECT 0.000000 96.590000 158.880000 96.910000 ;
      RECT 1.100000 95.690000 157.780000 96.590000 ;
      RECT 0.000000 95.370000 158.880000 95.690000 ;
      RECT 1.100000 94.470000 157.780000 95.370000 ;
      RECT 0.000000 94.150000 158.880000 94.470000 ;
      RECT 1.100000 93.250000 157.780000 94.150000 ;
      RECT 0.000000 92.930000 158.880000 93.250000 ;
      RECT 1.100000 92.030000 157.780000 92.930000 ;
      RECT 0.000000 91.710000 158.880000 92.030000 ;
      RECT 1.100000 90.810000 157.780000 91.710000 ;
      RECT 0.000000 90.490000 158.880000 90.810000 ;
      RECT 1.100000 89.590000 157.780000 90.490000 ;
      RECT 0.000000 89.270000 158.880000 89.590000 ;
      RECT 0.000000 88.660000 157.780000 89.270000 ;
      RECT 1.100000 88.370000 157.780000 88.660000 ;
      RECT 1.100000 88.050000 158.880000 88.370000 ;
      RECT 1.100000 87.760000 157.780000 88.050000 ;
      RECT 0.000000 87.440000 157.780000 87.760000 ;
      RECT 1.100000 87.150000 157.780000 87.440000 ;
      RECT 1.100000 86.830000 158.880000 87.150000 ;
      RECT 1.100000 86.540000 157.780000 86.830000 ;
      RECT 0.000000 86.220000 157.780000 86.540000 ;
      RECT 1.100000 85.930000 157.780000 86.220000 ;
      RECT 1.100000 85.610000 158.880000 85.930000 ;
      RECT 1.100000 85.320000 157.780000 85.610000 ;
      RECT 0.000000 85.000000 157.780000 85.320000 ;
      RECT 1.100000 84.710000 157.780000 85.000000 ;
      RECT 1.100000 84.390000 158.880000 84.710000 ;
      RECT 1.100000 84.100000 157.780000 84.390000 ;
      RECT 0.000000 83.780000 157.780000 84.100000 ;
      RECT 1.100000 83.490000 157.780000 83.780000 ;
      RECT 1.100000 83.170000 158.880000 83.490000 ;
      RECT 1.100000 82.880000 157.780000 83.170000 ;
      RECT 0.000000 82.560000 157.780000 82.880000 ;
      RECT 1.100000 82.270000 157.780000 82.560000 ;
      RECT 1.100000 81.660000 158.880000 82.270000 ;
      RECT 0.000000 81.340000 158.880000 81.660000 ;
      RECT 1.100000 80.440000 157.780000 81.340000 ;
      RECT 0.000000 80.120000 158.880000 80.440000 ;
      RECT 1.100000 79.220000 157.780000 80.120000 ;
      RECT 0.000000 78.900000 158.880000 79.220000 ;
      RECT 1.100000 78.000000 157.780000 78.900000 ;
      RECT 0.000000 77.680000 158.880000 78.000000 ;
      RECT 1.100000 76.780000 157.780000 77.680000 ;
      RECT 0.000000 76.460000 158.880000 76.780000 ;
      RECT 1.100000 75.560000 157.780000 76.460000 ;
      RECT 0.000000 75.240000 158.880000 75.560000 ;
      RECT 1.100000 74.340000 157.780000 75.240000 ;
      RECT 0.000000 74.020000 158.880000 74.340000 ;
      RECT 1.100000 73.120000 157.780000 74.020000 ;
      RECT 0.000000 72.800000 158.880000 73.120000 ;
      RECT 1.100000 71.900000 157.780000 72.800000 ;
      RECT 0.000000 71.580000 158.880000 71.900000 ;
      RECT 1.100000 70.680000 157.780000 71.580000 ;
      RECT 0.000000 70.360000 158.880000 70.680000 ;
      RECT 1.100000 69.460000 157.780000 70.360000 ;
      RECT 0.000000 69.140000 158.880000 69.460000 ;
      RECT 1.100000 68.240000 157.780000 69.140000 ;
      RECT 0.000000 67.920000 158.880000 68.240000 ;
      RECT 1.100000 67.020000 157.780000 67.920000 ;
      RECT 0.000000 66.700000 158.880000 67.020000 ;
      RECT 1.100000 65.800000 157.780000 66.700000 ;
      RECT 0.000000 65.480000 158.880000 65.800000 ;
      RECT 1.100000 64.870000 158.880000 65.480000 ;
      RECT 1.100000 64.580000 157.780000 64.870000 ;
      RECT 0.000000 64.260000 157.780000 64.580000 ;
      RECT 1.100000 63.970000 157.780000 64.260000 ;
      RECT 1.100000 63.650000 158.880000 63.970000 ;
      RECT 1.100000 63.360000 157.780000 63.650000 ;
      RECT 0.000000 63.040000 157.780000 63.360000 ;
      RECT 1.100000 62.750000 157.780000 63.040000 ;
      RECT 1.100000 62.430000 158.880000 62.750000 ;
      RECT 1.100000 62.140000 157.780000 62.430000 ;
      RECT 0.000000 61.820000 157.780000 62.140000 ;
      RECT 1.100000 61.530000 157.780000 61.820000 ;
      RECT 1.100000 61.210000 158.880000 61.530000 ;
      RECT 1.100000 60.920000 157.780000 61.210000 ;
      RECT 0.000000 60.310000 157.780000 60.920000 ;
      RECT 0.000000 59.990000 158.880000 60.310000 ;
      RECT 1.100000 59.380000 158.880000 59.990000 ;
      RECT 1.100000 59.090000 157.780000 59.380000 ;
      RECT 0.000000 58.770000 157.780000 59.090000 ;
      RECT 1.100000 58.480000 157.780000 58.770000 ;
      RECT 1.100000 58.160000 158.880000 58.480000 ;
      RECT 1.100000 57.870000 157.780000 58.160000 ;
      RECT 0.000000 57.550000 157.780000 57.870000 ;
      RECT 1.100000 57.260000 157.780000 57.550000 ;
      RECT 1.100000 56.940000 158.880000 57.260000 ;
      RECT 1.100000 56.650000 157.780000 56.940000 ;
      RECT 0.000000 56.330000 157.780000 56.650000 ;
      RECT 1.100000 56.040000 157.780000 56.330000 ;
      RECT 1.100000 55.720000 158.880000 56.040000 ;
      RECT 1.100000 55.430000 157.780000 55.720000 ;
      RECT 0.000000 55.110000 157.780000 55.430000 ;
      RECT 1.100000 54.820000 157.780000 55.110000 ;
      RECT 1.100000 54.500000 158.880000 54.820000 ;
      RECT 1.100000 54.210000 157.780000 54.500000 ;
      RECT 0.000000 53.890000 157.780000 54.210000 ;
      RECT 1.100000 53.600000 157.780000 53.890000 ;
      RECT 1.100000 53.280000 158.880000 53.600000 ;
      RECT 1.100000 52.990000 157.780000 53.280000 ;
      RECT 0.000000 52.670000 157.780000 52.990000 ;
      RECT 1.100000 52.380000 157.780000 52.670000 ;
      RECT 1.100000 52.060000 158.880000 52.380000 ;
      RECT 1.100000 51.770000 157.780000 52.060000 ;
      RECT 0.000000 51.450000 157.780000 51.770000 ;
      RECT 1.100000 51.160000 157.780000 51.450000 ;
      RECT 1.100000 50.840000 158.880000 51.160000 ;
      RECT 1.100000 50.550000 157.780000 50.840000 ;
      RECT 0.000000 50.230000 157.780000 50.550000 ;
      RECT 1.100000 49.940000 157.780000 50.230000 ;
      RECT 1.100000 49.620000 158.880000 49.940000 ;
      RECT 1.100000 49.330000 157.780000 49.620000 ;
      RECT 0.000000 49.010000 157.780000 49.330000 ;
      RECT 1.100000 48.720000 157.780000 49.010000 ;
      RECT 1.100000 48.400000 158.880000 48.720000 ;
      RECT 1.100000 48.110000 157.780000 48.400000 ;
      RECT 0.000000 47.790000 157.780000 48.110000 ;
      RECT 1.100000 47.500000 157.780000 47.790000 ;
      RECT 1.100000 47.180000 158.880000 47.500000 ;
      RECT 1.100000 46.890000 157.780000 47.180000 ;
      RECT 0.000000 46.570000 157.780000 46.890000 ;
      RECT 1.100000 46.280000 157.780000 46.570000 ;
      RECT 1.100000 45.670000 158.880000 46.280000 ;
      RECT 0.000000 45.350000 158.880000 45.670000 ;
      RECT 1.100000 44.450000 158.880000 45.350000 ;
      RECT 0.000000 44.130000 158.880000 44.450000 ;
      RECT 1.100000 43.230000 158.880000 44.130000 ;
      RECT 0.000000 42.910000 158.880000 43.230000 ;
      RECT 1.100000 42.010000 158.880000 42.910000 ;
      RECT 0.000000 41.690000 158.880000 42.010000 ;
      RECT 1.100000 40.790000 158.880000 41.690000 ;
      RECT 0.000000 0.000000 158.880000 40.790000 ;
    LAYER met4 ;
      RECT 112.620000 146.160000 158.880000 147.260000 ;
      RECT 111.390000 146.160000 111.720000 147.260000 ;
      RECT 110.160000 146.160000 110.490000 147.260000 ;
      RECT 108.930000 146.160000 109.260000 147.260000 ;
      RECT 107.700000 146.160000 108.030000 147.260000 ;
      RECT 106.470000 146.160000 106.800000 147.260000 ;
      RECT 105.240000 146.160000 105.570000 147.260000 ;
      RECT 104.010000 146.160000 104.340000 147.260000 ;
      RECT 102.780000 146.160000 103.110000 147.260000 ;
      RECT 101.550000 146.160000 101.880000 147.260000 ;
      RECT 100.320000 146.160000 100.650000 147.260000 ;
      RECT 99.090000 146.160000 99.420000 147.260000 ;
      RECT 97.860000 146.160000 98.190000 147.260000 ;
      RECT 96.630000 146.160000 96.960000 147.260000 ;
      RECT 95.400000 146.160000 95.730000 147.260000 ;
      RECT 94.170000 146.160000 94.500000 147.260000 ;
      RECT 92.940000 146.160000 93.270000 147.260000 ;
      RECT 91.710000 146.160000 92.040000 147.260000 ;
      RECT 90.480000 146.160000 90.810000 147.260000 ;
      RECT 89.250000 146.160000 89.580000 147.260000 ;
      RECT 87.405000 146.160000 88.350000 147.260000 ;
      RECT 86.175000 146.160000 86.505000 147.260000 ;
      RECT 84.945000 146.160000 85.275000 147.260000 ;
      RECT 83.715000 146.160000 84.045000 147.260000 ;
      RECT 82.485000 146.160000 82.815000 147.260000 ;
      RECT 81.255000 146.160000 81.585000 147.260000 ;
      RECT 80.025000 146.160000 80.355000 147.260000 ;
      RECT 78.180000 146.160000 79.125000 147.260000 ;
      RECT 76.335000 146.160000 77.280000 147.260000 ;
      RECT 75.105000 146.160000 75.435000 147.260000 ;
      RECT 73.875000 146.160000 74.205000 147.260000 ;
      RECT 72.645000 146.160000 72.975000 147.260000 ;
      RECT 71.415000 146.160000 71.745000 147.260000 ;
      RECT 69.570000 146.160000 70.515000 147.260000 ;
      RECT 67.725000 146.160000 68.670000 147.260000 ;
      RECT 66.495000 146.160000 66.825000 147.260000 ;
      RECT 64.650000 146.160000 65.595000 147.260000 ;
      RECT 62.805000 146.160000 63.750000 147.260000 ;
      RECT 61.575000 146.160000 61.905000 147.260000 ;
      RECT 60.345000 146.160000 60.675000 147.260000 ;
      RECT 59.115000 146.160000 59.445000 147.260000 ;
      RECT 57.885000 146.160000 58.215000 147.260000 ;
      RECT 56.655000 146.160000 56.985000 147.260000 ;
      RECT 55.425000 146.160000 55.755000 147.260000 ;
      RECT 54.195000 146.160000 54.525000 147.260000 ;
      RECT 52.965000 146.160000 53.295000 147.260000 ;
      RECT 51.735000 146.160000 52.065000 147.260000 ;
      RECT 50.505000 146.160000 50.835000 147.260000 ;
      RECT 49.275000 146.160000 49.605000 147.260000 ;
      RECT 48.045000 146.160000 48.375000 147.260000 ;
      RECT 46.815000 146.160000 47.145000 147.260000 ;
      RECT 45.585000 146.160000 45.915000 147.260000 ;
      RECT 44.355000 146.160000 44.685000 147.260000 ;
      RECT 0.000000 146.160000 43.455000 147.260000 ;
      RECT 0.000000 1.100000 158.880000 146.160000 ;
      RECT 112.620000 0.000000 158.880000 1.100000 ;
      RECT 111.390000 0.000000 111.720000 1.100000 ;
      RECT 110.160000 0.000000 110.490000 1.100000 ;
      RECT 108.930000 0.000000 109.260000 1.100000 ;
      RECT 107.700000 0.000000 108.030000 1.100000 ;
      RECT 106.470000 0.000000 106.800000 1.100000 ;
      RECT 105.240000 0.000000 105.570000 1.100000 ;
      RECT 104.010000 0.000000 104.340000 1.100000 ;
      RECT 102.780000 0.000000 103.110000 1.100000 ;
      RECT 101.550000 0.000000 101.880000 1.100000 ;
      RECT 99.705000 0.000000 100.650000 1.100000 ;
      RECT 98.475000 0.000000 98.805000 1.100000 ;
      RECT 96.630000 0.000000 97.575000 1.100000 ;
      RECT 95.400000 0.000000 95.730000 1.100000 ;
      RECT 94.170000 0.000000 94.500000 1.100000 ;
      RECT 92.940000 0.000000 93.270000 1.100000 ;
      RECT 91.710000 0.000000 92.040000 1.100000 ;
      RECT 90.480000 0.000000 90.810000 1.100000 ;
      RECT 89.250000 0.000000 89.580000 1.100000 ;
      RECT 88.020000 0.000000 88.350000 1.100000 ;
      RECT 86.175000 0.000000 87.120000 1.100000 ;
      RECT 84.945000 0.000000 85.275000 1.100000 ;
      RECT 83.100000 0.000000 84.045000 1.100000 ;
      RECT 81.870000 0.000000 82.200000 1.100000 ;
      RECT 80.640000 0.000000 80.970000 1.100000 ;
      RECT 78.795000 0.000000 79.740000 1.100000 ;
      RECT 77.565000 0.000000 77.895000 1.100000 ;
      RECT 75.720000 0.000000 76.665000 1.100000 ;
      RECT 73.875000 0.000000 74.820000 1.100000 ;
      RECT 72.645000 0.000000 72.975000 1.100000 ;
      RECT 71.415000 0.000000 71.745000 1.100000 ;
      RECT 69.570000 0.000000 70.515000 1.100000 ;
      RECT 68.340000 0.000000 68.670000 1.100000 ;
      RECT 67.110000 0.000000 67.440000 1.100000 ;
      RECT 65.880000 0.000000 66.210000 1.100000 ;
      RECT 64.650000 0.000000 64.980000 1.100000 ;
      RECT 63.420000 0.000000 63.750000 1.100000 ;
      RECT 62.190000 0.000000 62.520000 1.100000 ;
      RECT 60.960000 0.000000 61.290000 1.100000 ;
      RECT 59.730000 0.000000 60.060000 1.100000 ;
      RECT 58.500000 0.000000 58.830000 1.100000 ;
      RECT 57.270000 0.000000 57.600000 1.100000 ;
      RECT 56.040000 0.000000 56.370000 1.100000 ;
      RECT 54.810000 0.000000 55.140000 1.100000 ;
      RECT 53.580000 0.000000 53.910000 1.100000 ;
      RECT 52.350000 0.000000 52.680000 1.100000 ;
      RECT 50.505000 0.000000 51.450000 1.100000 ;
      RECT 49.275000 0.000000 49.605000 1.100000 ;
      RECT 48.045000 0.000000 48.375000 1.100000 ;
      RECT 46.815000 0.000000 47.145000 1.100000 ;
      RECT 45.585000 0.000000 45.915000 1.100000 ;
      RECT 44.355000 0.000000 44.685000 1.100000 ;
      RECT 43.125000 0.000000 43.455000 1.100000 ;
      RECT 41.895000 0.000000 42.225000 1.100000 ;
      RECT 0.000000 0.000000 40.995000 1.100000 ;
    LAYER met5 ;
      RECT 0.000000 105.250000 158.880000 147.260000 ;
      RECT 4.100000 100.450000 158.880000 105.250000 ;
      RECT 0.000000 97.930000 158.880000 100.450000 ;
      RECT 4.100000 93.130000 154.780000 97.930000 ;
      RECT 0.000000 90.610000 158.880000 93.130000 ;
      RECT 4.100000 85.810000 154.780000 90.610000 ;
      RECT 0.000000 83.290000 158.880000 85.810000 ;
      RECT 0.000000 79.630000 154.780000 83.290000 ;
      RECT 4.100000 78.490000 154.780000 79.630000 ;
      RECT 4.100000 75.970000 158.880000 78.490000 ;
      RECT 4.100000 74.830000 154.780000 75.970000 ;
      RECT 0.000000 72.310000 154.780000 74.830000 ;
      RECT 4.100000 71.170000 154.780000 72.310000 ;
      RECT 4.100000 67.510000 158.880000 71.170000 ;
      RECT 0.000000 64.990000 158.880000 67.510000 ;
      RECT 0.000000 61.330000 154.780000 64.990000 ;
      RECT 4.100000 60.190000 154.780000 61.330000 ;
      RECT 4.100000 57.670000 158.880000 60.190000 ;
      RECT 4.100000 56.530000 154.780000 57.670000 ;
      RECT 0.000000 54.010000 154.780000 56.530000 ;
      RECT 4.100000 52.870000 154.780000 54.010000 ;
      RECT 4.100000 50.350000 158.880000 52.870000 ;
      RECT 4.100000 49.210000 154.780000 50.350000 ;
      RECT 0.000000 46.690000 154.780000 49.210000 ;
      RECT 4.100000 45.550000 154.780000 46.690000 ;
      RECT 4.100000 41.890000 158.880000 45.550000 ;
      RECT 0.000000 0.000000 158.880000 41.890000 ;
  END
END memory_macro

END LIBRARY
